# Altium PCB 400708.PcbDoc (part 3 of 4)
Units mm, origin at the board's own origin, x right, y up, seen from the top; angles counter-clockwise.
Board outline 117 x 63.5 mm, 4 copper layers (Top Layer, Mid-Layer 1, Mid-Layer 2, Bottom Layer), stack 1.556 mm thick; 207 components, 162 nets, 822 pads, 1266 vias.
Unrouted connection lines stored in the file: 43.

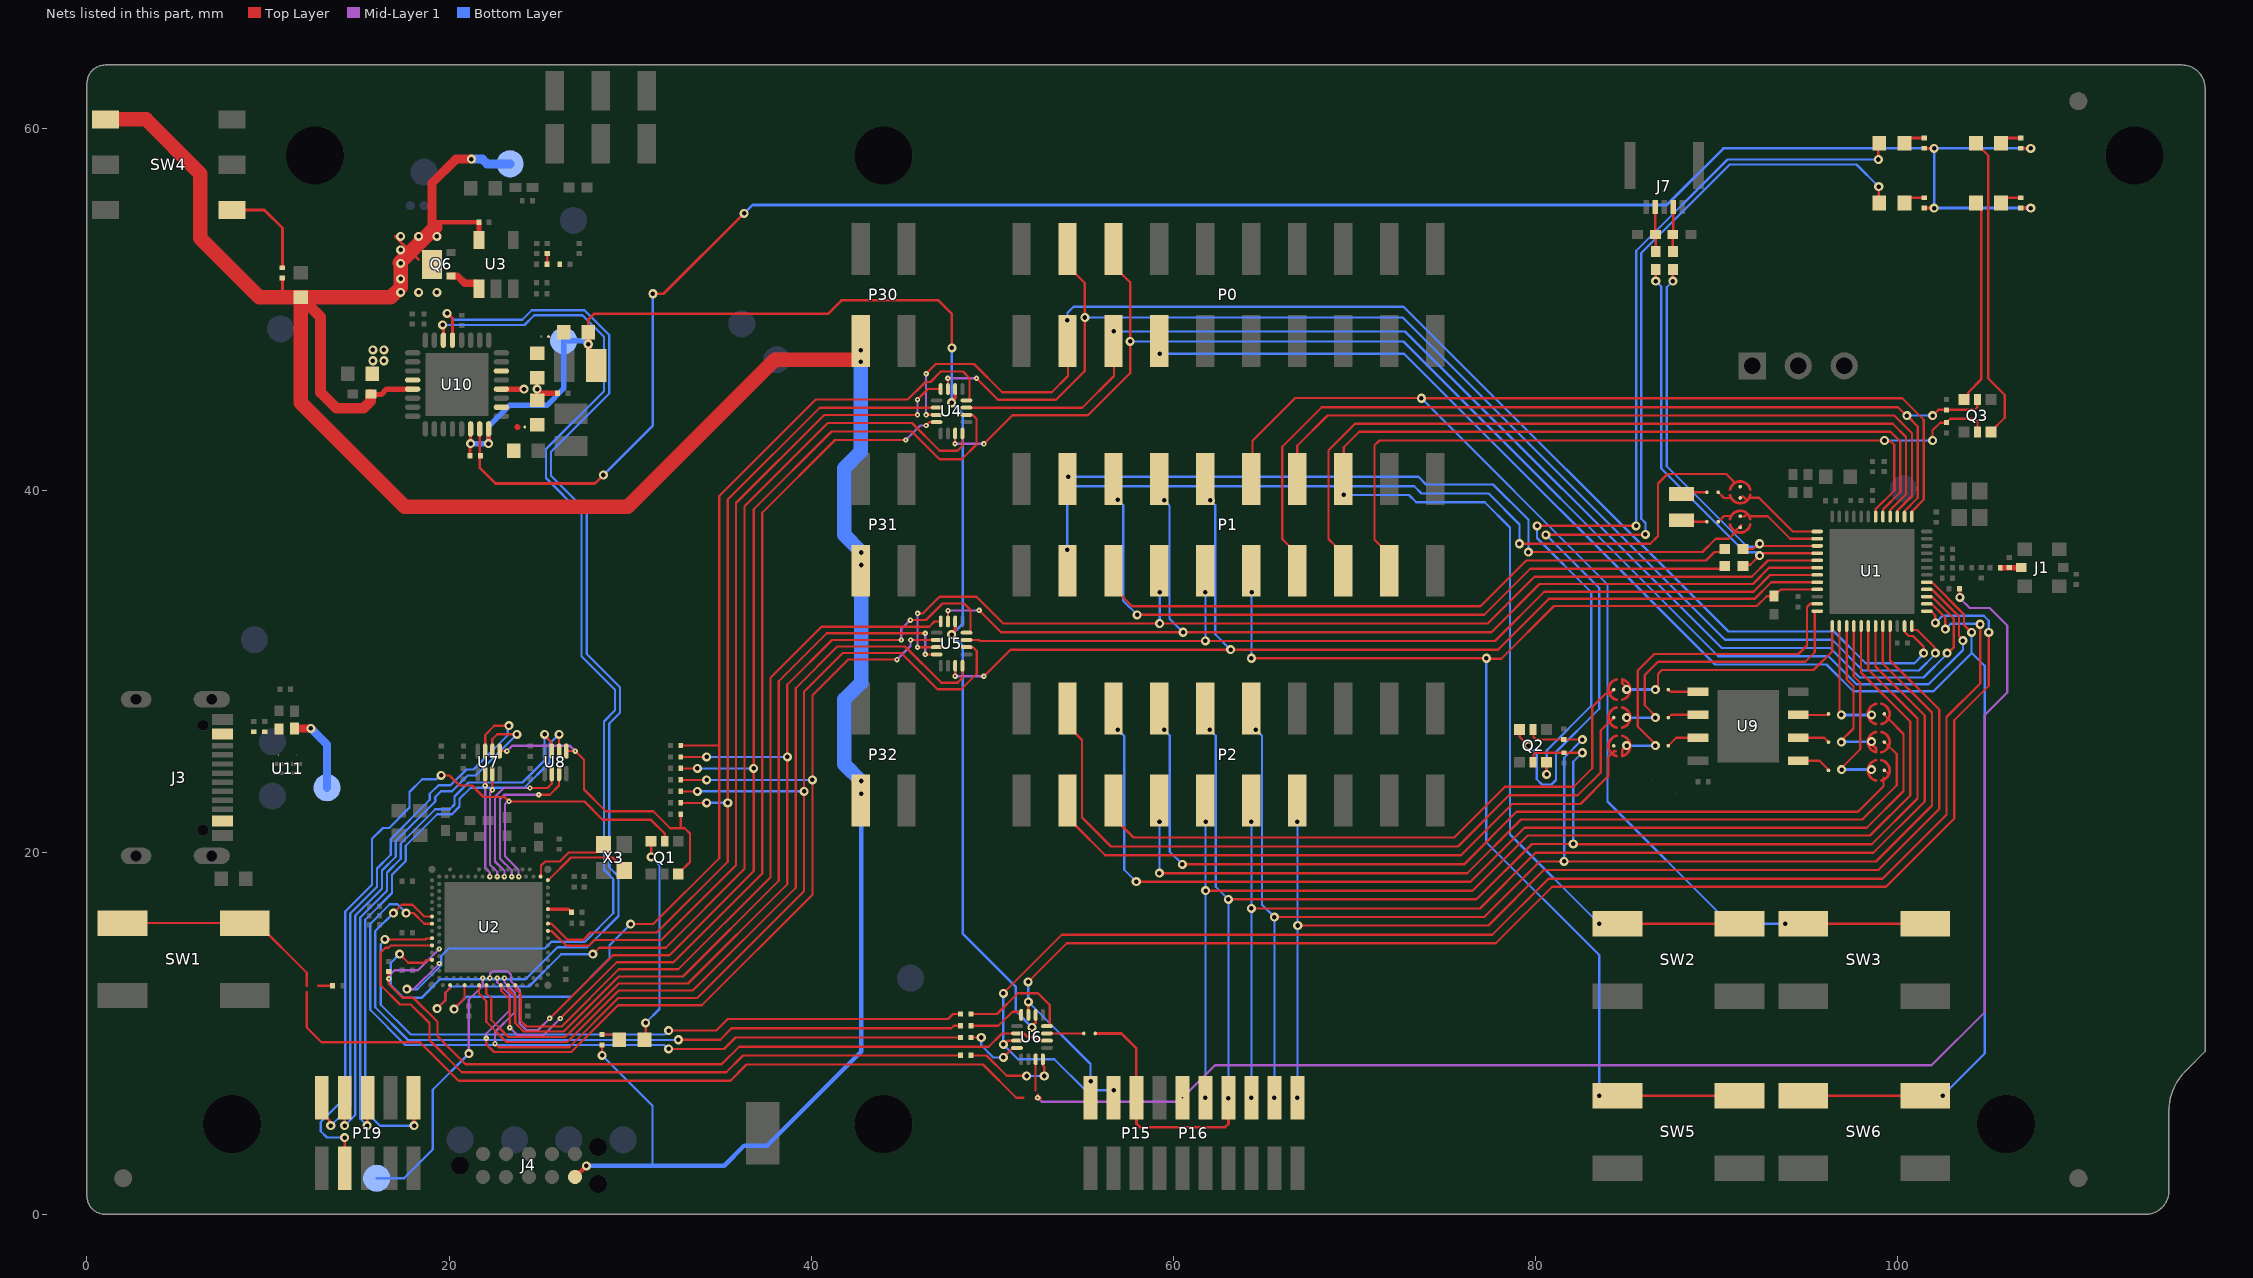
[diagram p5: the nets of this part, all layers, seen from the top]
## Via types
v1: diameter 0.5, hole 0.25, Top Layer to Bottom Layer, tented both sides, 1159 vias
v2: diameter 0.3, hole 0.1, Top Layer to Mid-Layer 1, tented top, 61 vias
v3: diameter 0.61, hole 0.305, Top Layer to Bottom Layer, tented both sides, 28 vias
v4: diameter 0.61, hole 0.305, Top Layer to Bottom Layer, 9 vias
v5: diameter 0.3, hole 0.1, Top Layer to Mid-Layer 1, tented both sides, 9 vias

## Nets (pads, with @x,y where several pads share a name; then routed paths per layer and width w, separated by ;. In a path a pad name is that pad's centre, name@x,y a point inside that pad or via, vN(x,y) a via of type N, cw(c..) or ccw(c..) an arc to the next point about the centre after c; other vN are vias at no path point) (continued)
NetLD1_1: LD1.1 Q1.6 | length 11.5
  Top Layer w0.125: LD1.1@30.865,9.716 v1(30.865,10.588)
  Top Layer w0.15: LD1.1@30.802,9.652 LD1.1@30.865,9.716 ; v1(31.165,19.75) Q1.6@31.165,20.615
  Bottom Layer w0.125: v1(30.865,10.588) 31.627,11.35 31.627,19.287 v1(31.165,19.75)
NetLD1_2: LD1.2 R5.1 | length 0.9
  Top Layer w0.125: R5.1@28.579,9.937 29.12,9.937 LD1.2@29.405,9.652
NetLD2_1: LD2.1 Q2.6 | length 53.7
  Top Layer w0.125: v1(80.106,38.04) 80.11,38.044 v1(85.582,38.044) ; v1(80.634,24.308) Q2.6@80.634,24.985
  Top Layer w0.15: v1(98.955,58.278) 98.955,59.127 LD2.1@99.01,59.182
  Bottom Layer w0.125: v1(80.106,38.04) 80.106,37.375 83.105,34.376 83.105,28.108 80.634,25.637 v1(80.634,24.308) ; v1(85.582,38.044) 85.582,53.231 90.629,58.278 v1(98.955,58.278)
NetLD2_2: LD2.2 R19.1 | length 1.2
  Top Layer w0.15: LD2.2@100.407,59.182 100.692,59.467 R19.1@101.487,59.467
NetLD3_1: LD3.1 Q3.6 | length 16.9
  Top Layer w0.125: LD3.1@104.344,59.182 104.344,59.157 104.663,58.838 104.688,58.838 104.997,58.529 105.034,58.492 105.034,46.174 105.935,45.273 105.935,44.005 Q3.6@105.185,43.255
NetLD3_2: LD3.2 R20.1 | length 1.2
  Top Layer w0.15: LD3.2@105.741,59.182 106.026,59.467 R20.1@106.821,59.467
NetLD4_1: LD4.1 Q2.3 | length 57.9
  Top Layer w0.125: Q2.3@79.134,26.785 79.155,26.763 79.155,26.37 v1(79.63,25.896) ; v1(80.598,37.544) 86.071,37.544 v1(86.09,37.563)
  Top Layer w0.15: v1(98.98,56.778) 98.98,55.91 LD4.1@99.01,55.88
  Bottom Layer w0.125: v1(79.63,25.896) 80.084,25.441 80.084,24.046 80.381,23.749 80.903,23.749 81.157,24.003 81.157,25.553 83.535,27.93 83.535,34.607 v1(80.598,37.544) ; v1(86.09,37.563) 86.09,38.202 85.857,38.434 85.857,53.117 90.743,58.003 97.755,58.003 v1(98.98,56.778)
NetLD4_2: LD4.2 R1.1 | length 0.8
  Top Layer w0.15: LD4.2@100.692,56.165 R1.1@101.487,56.165
NetLD5_1: LD5.1 Q3.3 | length 11.4
  Top Layer w0.125: Q3.3@103.685,45.03 103.918,45.263 103.918,45.412 104.653,46.147 ; LD5.1@104.344,55.88 104.648,55.577 104.648,46.147
NetLD5_2: LD5.2 R2.1 | length 0.8
  Top Layer w0.15: LD5.2@106.026,56.165 R2.1@106.821,56.165
NetP1_5: P1.5 R33.2 | length 36.7
  Top Layer w0.125: P1.5@56.729,35.877 56.729,34.607 57.734,33.603 76.985,33.603 79.509,36.128 89.44,36.128 89.903,36.591 90.309,36.591 R33.2@90.474,36.755
NetP1_6: P1.6 R34.2 | length 41.6
  Top Layer w0.125: P1.6@56.704,40.64 56.704,39.721 v1(56.95,39.475) ; v1(58.012,33.128) 77.181,33.128 79.726,35.672 90.316,35.672 R34.2@90.474,35.83
  Bottom Layer w0.125: v1(56.95,39.475) 57.25,39.175 57.25,33.89 v1(58.012,33.128)
NetP2_3: P2.3 SB17.1 | length 35.4
  Top Layer w0.125: P2.3@54.189,23.177 54.189,21.907 P2.3@54.61,21.487 ; P2.3@54.61,21.487 56.248,19.849 75.903,19.849 78.73,22.676 82.5,22.676 84.042,24.219 84.042,25.272 84.233,25.463
  Top Layer w0.152: 84.233,25.463 84.354,25.584 84.443,25.584
NetP2_4: P2.4 SB18.1 | length 40.3
  Top Layer w0.125: P2.4@54.189,27.556 54.189,26.988 54.61,26.567 54.968,26.209 54.968,21.932 56.571,20.329 75.733,20.329 78.556,23.152 82.35,23.152 83.618,24.42 83.618,26.731 84.1,27.213
  Top Layer w0.152: 84.1,27.213 SB18.1@84.34,27.453
NetP2_5: P2.5 SB19.1 | length 34.5
  Top Layer w0.125: P2.5@56.729,22.956 56.729,21.908 57.15,21.487 57.809,20.828 75.532,20.828 78.335,23.631 82.132,23.631 83.158,24.657 83.158,28.037 83.877,28.756 84.1,28.756
  Top Layer w0.152: 84.1,28.756 SB19.1@84.34,28.996
NetP2_6: P2.6 SB20.1 | length 58.8
  Top Layer w0.125: v1(57.965,18.382) 76.424,18.382 79.406,21.364 98.319,21.364 100.353,23.397 100.353,26.547 99.53,27.37 SB20.1@99.29,27.61
  Top Layer w0.15: P2.6@56.729,27.556 56.729,26.996 v1(56.95,26.775)
  Bottom Layer w0.125: v1(56.95,26.775) 57.3,26.425 57.3,19.046 v1(57.965,18.382)
NetP2_7: P2.7 SB21.1 | length 48.3
  Top Layer w0.125: v1(59.241,18.853) 76.244,18.853 79.212,21.821 98.074,21.821 99.968,23.715 99.968,25.433 99.53,25.871 SB21.1@99.29,26.111
  Bottom Layer w0.125: v1(59.241,18.853) 59.245,18.857 59.245,21.696 v1(59.248,21.7)
NetP2_8: P2.8 SB22.1 | length 49.2
  Top Layer w0.125: v1@60.516,19.34 76.069,19.34 78.973,22.244 97.827,22.244 99.238,23.655 99.238,24.008 99.292,24.062 99.298,24.069 99.236,24.13 ; SB22.1@99.29,24.562 99.53,24.322
  Bottom Layer w0.125: v1(59.5,26.775) 59.819,26.456 59.819,20.037 v1(60.515,19.341)
NetQ1_3: Q1.3 R8.1 U7.5 U8.5 | length 17.4
  Top Layer w0.125: U7.5@22.795,25.599 v2@23.189,25.599 ; U8.5@26.478,25.599 v2(26.969,25.599) 26.971,25.599 27.454,25.116 27.454,23.477 28.656,22.275 31.288,22.275 32.227,21.336 32.772,21.336 ; Q1.3@32.665,18.815 33.316,19.467 33.316,21.044 33.024,21.336 32.772,21.336 ; R8.1@32.801,22.098 32.801,21.365 32.772,21.336
  Mid-Layer 1 w0.125: v2(23.195,25.599) 23.482,25.886 26.682,25.886 v2(26.969,25.599)
NetQ6_1: Q6.1 U3.1 | length 2
  Top Layer w0.4: Q6.1@20.099,51.836 20.474,51.836 20.874,51.436 21.549,51.436 21.649,51.336 U3.1@21.649,51.136
NetR1_2: R1.2 R2.2 R19.2 R20.2 R54.1 U10.31 | length 111
  Top Layer w0.15: U10.31@21.692,43.396 21.692,41.255 22.567,40.379 28.054,40.379 v1(28.525,40.85) ; v1(31.257,50.861) 31.849,50.861 36.293,55.305 v1(36.304,55.305) ; R1.2@101.487,55.595 v1(102.042,55.595) ; R19.2@101.487,58.897 v1(102.042,58.897) ; R2.2@106.821,55.595 v1(107.376,55.595) ; R20.2@106.821,58.897 v1(107.376,58.897)
  Bottom Layer w0.15: v1(28.525,40.85) 31.257,43.582 v1(31.257,50.861) ; v1(36.304,55.305) 36.762,55.763 87.267,55.763 90.401,58.897 v1(102.042,58.897) ; v1(107.376,55.595) v1(102.042,55.595) v1(102.042,58.897) ; v1(107.376,58.897) v1(102.042,58.897)
NetR4_2: R4.2 U6.16 | length 3.3
  Top Layer w0.125: R4.2@48.835,10.425 50.342,10.425 51.121,11.204 51.572,11.204 51.604,11.172 U6.16@51.604,11.025
NetR7_1: R7.1 U2.L31 | length 1.4
  Top Layer w0.187: U2.L31@25.46,16.864 26.597,16.864 26.719,16.743 26.734,16.743 26.775,16.702 R7.1@26.775,16.687
NetR9_2: R9.2 U6.4 | length 3.5
  Top Layer w0.125: R9.2@48.835,9.776 v1(49.402,9.776) ; v1(50.619,8.676) 51.142,9.2 U6.4@51.379,9.2
  Bottom Layer w0.125: v1(49.402,9.776) 49.402,9.344 50.069,8.676 v1(50.619,8.676)
NetR23_1: R23.1 SB8.2 | length 0.8
  Top Layer w0.125: 12.763,12.635 12.764,12.634 12.937,12.634 R23.1@13.569,12.634
NetR31_2: R31.2 R32.2 R35.1 | length 0.5
  Top Layer w0.125: R31.2@25.424,52.595 R32.2@25.424,53.076
NetR36_1: R36.1 SW4.4 | length 5.8
  Top Layer w0.15: SW4.4@8.29,55.219 SW4.4@8.021,55.488 9.794,55.488 10.799,54.483 R36.1@10.799,52.296
NetR37_2: R37.2 U6.12 | length 6.4
  Top Layer w0.125: R37.2@48.835,11.075 50.268,11.075 51.411,12.218 52.539,12.218 53.189,11.568 53.189,10.444 53.146,10.4 U6.12@53.029,10.4
NetR38_2: R38.2 U6.8 | length 5.5
  Top Layer w0.125: R38.2@48.835,8.784 49.685,8.784 50.812,7.657 51.895,7.657 v1(51.902,7.65) ; U6.8@52.804,8.575 52.822,8.557 52.822,8.22 52.882,8.16 v1(52.882,7.65)
  Bottom Layer w0.125: v1(51.902,7.65) v1(52.882,7.65)
NetSB1_2: SB1.2 SB2.1 SB8.1 SW1.2 | length 55.9
  Top Layer w0.125: SW1.2@1.963,16.097 SW1.2@8.713,16.097 9.388,16.097 12.138,13.347 12.138,12.988 12.138,12.635 ; 12.138,12.282 12.138,10.328 12.95,9.516 18.401,9.516 20.523,7.393 35.55,7.393 36.439,8.282 49.5,8.282 51.332,6.45 51.718,6.45
NetSB3_2: SB3.2 X1.2 | length 1.4
  Top Layer w0.125: X1.2@88.081,39.799 88.175,39.893 SB3.2@89.488,39.893
NetSB4_2: SB4.2 X1.1 | length 1.4
  Top Layer w0.125: X1.1@88.081,38.349 88.162,38.267 SB4.2@89.488,38.267
NetSB11_2: SB11.2 U9.1 | length 1.9
  Top Layer w0.125: U9.1@94.536,25.066 95.708,25.066 SB11.2@96.203,24.571
NetSB12_2: SB12.2 U9.6 | length 1.7
  Top Layer w0.125: SB12.2@87.353,27.446 87.513,27.606 U9.6@88.996,27.606
NetSB13_2: SB13.2 U9.5 | length 1.7
  Top Layer w0.125: SB13.2@87.353,28.996 87.473,28.876 U9.5@88.996,28.876
NetSB14_2: SB14.2 U9.2 | length 1.8
  Top Layer w0.125: U9.2@94.536,26.336 95.963,26.336 SB14.2@96.203,26.096
NetSB15_2: SB15.2 U9.3 | length 1.7
  Top Layer w0.125: U9.3@94.536,27.606 94.546,27.596 SB15.2@96.203,27.596
NetSB16_2: SB16.2 U9.7 | length 1.8
  Top Layer w0.125: SB16.2@87.353,25.896 87.793,26.336 U9.7@88.996,26.336
NetSB24_1: SB24.1 U6.11 | length 2
  Top Layer w0.125: U6.11@53.029,10 SB24.1@55.067,10
NetTP7_1: TP7.1 U2.AK14 | length 14.4
  Mid-Layer 1 w0.125: v1(21.097,8.889) 21.092,8.895 21.092,11.861 21.86,12.629 v2(21.86,13.064)
  Bottom Layer w0.125: TP7.1@16.004,2 17.52,2 19.104,3.584 19.104,6.897 v1(21.097,8.889)
NetU2_B30: U2.B30 X3.3 | length 4.6
  Top Layer w0.125: U2.B30@25.06,18.664 25.079,18.684 25.079,18.754 25.085,18.76 25.085,19.273 25.315,19.502 26.123,19.502 26.61,19.99 28.127,19.99 28.531,20.394 X3.3@28.531,20.444
NetU2_C31: U2.C31 X3.1 | length 5.1
  Top Layer w0.125: U2.C31@25.46,18.464 25.485,18.464 26.735,19.715 29.027,19.715 29.681,19.061 X3.1@29.681,18.994
NFC1: C17.1 J7.2 R21.2 | length 2.5
  Top Layer w0.125: R21.2@87.604,53.204 C17.1@87.604,54.123 87.629,54.148 J7.2@87.629,55.654
NFC2: C19.2 J7.4 R22.2 | length 2.5
  Top Layer w0.125: J7.4@86.629,55.654 86.629,54.146 C19.2@86.652,54.123 86.661,54.114 R22.2@86.661,53.204
nRF54L15_RESET: P15.10 P16.10 R3.2 SB1.1 U6.7 | length 82.3
  Top Layer w0.125: v2@52.404,6.379 v2@52.404,6.45 ; 52.404,6.866 U6.7@52.404,8.575 ; v2(52.515,6.45) 52.518,6.447 52.671,6.447 52.691,6.427 v2@52.593,6.427 ; R3.2@103.435,34.575 103.447,34.563 103.447,34.105 v1(103.459,34.093)
  Top Layer w0.15: v2(52.515,6.45) 52.515,6.608 52.517,6.61
  Mid-Layer 1 w0.125: v2(52.515,6.45) 52.742,6.223 60.291,6.223 v2(60.518,6.45) 62.308,8.239 101.896,8.239 104.835,11.178 104.835,27.598 106.077,28.84 106.077,32.531 105.108,33.5 104,33.5 103.459,34.041 v1(103.459,34.093)
P0.00: P0.3 U1.23 U4.3 | length 73.4
  Top Layer w0.125: v2(46.353,44.171) U4.3@46.935,44.171 ; v2(46.353,46.446) 46.887,46.98 49,46.98 50.559,45.421 53.293,45.421 54.189,46.317 54.189,48.577 54.154,48.613 54.154,49.393 v1(54.164,49.403) ; U1.23@100.414,32.496 100.414,32.172 100.633,31.953 100.875,31.953 101.453,31.375 101.453,31.007 v1(101.455,31.005)
  Mid-Layer 1 w0.125: v2(46.353,44.171) v2(46.353,46.446)
  Bottom Layer w0.125: v1(54.164,49.403) 54.164,49.814 54.5,50.15 72.73,50.15 90.682,32.198 96.512,32.198 98.255,30.455 100.956,30.455 101.455,30.954 v1(101.455,31.005)
P0.01: P0.4 U1.24 U4.15 | length 74
  Top Layer w0.125: U4.15@47.56,45.597 v2(47.559,46.193) ; v2(49.139,46.193) 50.326,45.006 53.531,45.006 55.125,46.601 55.125,51.452 54.61,51.967 54.189,52.388 P0.4@54.189,53.222 ; U1.24@100.805,32.505 100.805,32.307 100.828,32.284 101.102,32.284 102.057,31.328 102.057,31.053 v1(102.105,31.005)
  Mid-Layer 1 w0.125: v2(47.559,46.193) v2(49.139,46.193)
  Bottom Layer w0.125: v1(55.125,49.55) 72.686,49.55 90.493,31.743 96.408,31.743 98.103,30.048 101.203,30.048 102.105,30.951 v1(102.105,31.005)
P0.02: P0.5 U1.27 U4.11 | length 69.9
  Top Layer w0.125: U4.11@48.585,44.571 54.983,44.571 56.729,46.317 v1(56.729,48.778) ; U1.27@101.639,34.121 101.885,34.121 101.913,34.093 101.944,34.093 103.13,32.906 103.13,31.343 102.795,31.007 v1(102.76,31.007)
  Bottom Layer w0.125: v1(56.729,48.778) 72.815,48.778 90.305,31.288 96.304,31.288 97.925,29.667 101.448,29.667 102.76,30.979 v1(102.76,31.007)
P0.03: P0.6 U1.28 U4.7 | length 78
  Top Layer w0.125: v2@47.955,42.582 U4.7@47.955,43.141 ; U4.7@47.964,43.125 U4.7@47.971,43.118 ; v2(49.545,42.564) 51.127,44.146 55.296,44.146 57.625,46.475 57.625,51.492 56.729,52.388 P0.6@56.729,53.222 ; U1.28@101.63,34.53 101.876,34.53 101.913,34.493 101.946,34.493 103.411,33.027 103.411,31.966 103.63,31.747 v1(103.63,31.705)
  Top Layer w0.152: v2(47.95,42.577) v2@47.955,42.582
  Mid-Layer 1 w0.125: v2(47.95,42.577) 47.957,42.571 v2@49.539,42.571
  Bottom Layer w0.125: v1(57.625,48.225) 72.724,48.225 90.116,30.833 96.201,30.833 97.747,29.286 101.733,29.286 103.63,31.183 v1(103.63,31.705)
P0.04: P0.7 SW6.2 U1.29 | length 93
  Top Layer w0.125: U1.29@101.639,34.921 101.885,34.921 101.913,34.893 101.944,34.893 103.694,33.142 103.694,32.566 v1(104.105,32.155)
  Top Layer w0.15: v1(59.269,47.549) P0.7@59.269,48.577 ; SW6.2@94.804,6.558 v1(102.504,6.558)
  Bottom Layer w0.125: v1(59.269,47.549) 72.757,47.549 89.928,30.378 96.097,30.378 97.57,28.905 102.01,28.905 104.105,31.001 104.105,31.034 ; v1(102.504,6.558) 104.835,8.888 104.835,30.305 104.105,31.034 ; v1(104.105,32.155) 104.105,31.034
P1.00: P1.3 SB5.2 | length 45.6
  Top Layer w0.125: v1@79.109,37.076 v1(79.134,37.052) v1(79.134,37.052) 86.358,37.053 86.782,37.477 86.782,40.38 87.31,40.908 90.558,40.908 91.045,40.421
  Bottom Layer w0.125: v1(54.15,36.725) 54.15,39.825 54.55,40.225 73.326,40.225 73.726,39.825 77.431,39.825 79.134,38.122 v1(79.134,37.052)
P1.00/XL1: SB3.1 SB5.1 U1.1 | length 5.8
  Top Layer w0.125: SB3.1@90.112,39.893 90.425,39.581 90.826,39.581 ; SB5.1@91.324,39.581 91.338,39.581 91.402,39.645 91.513,39.645 91.714,39.444 91.715,39.443 ; 91.863,39.591 92.37,39.591 94.231,37.73 U1.1@95.58,37.73
P1.01: P1.4 SB6.2 | length 40.7
  Top Layer w0.125: v1(79.63,36.591) 89.242,36.591 89.981,37.33 90.69,37.33 91.062,37.703 ; 91.045,37.74 91.383,38.078 ; 91.077,37.708 91.088,37.718
  Top Layer w0.15: P1.4@54.164,40.64 54.2,40.676 v1(54.2,40.75)
  Bottom Layer w0.125: v1(54.2,40.75) 73.55,40.75 73.975,40.325 77.676,40.325 79.63,38.371 v1(79.63,36.591)
P1.01/XL2: SB4.1 SB6.1 U1.2 | length 5.8
  Top Layer w0.125: SB4.1@90.112,38.267 90.425,38.58 90.826,38.58 ; SB6.1@91.324,38.58 91.334,38.57 91.369,38.57 91.384,38.555 91.568,38.555 91.722,38.709 ; 91.697,38.734 91.722,38.709 ; 91.723,38.71 91.722,38.709 ; U1.2@95.58,37.33 94.091,37.33 92.851,38.57 91.861,38.57 91.85,38.581 91.722,38.709
P1.02/NFC1: R21.1 R33.1 U1.3 | length 22.2
  Top Layer w0.125: v1(87.604,51.554) R21.1@87.604,52.204 ; R33.1@91.577,36.755 92.043,36.755 92.34,37.052 v1(92.399,37.052) 92.494,37.052 92.615,36.93 U1.3@95.58,36.93
  Bottom Layer w0.125: v1(87.604,51.554) 87.264,51.214 87.264,41.339 91.722,36.881 92.228,36.881 v1(92.399,37.052)
P1.03/NFC2: R22.1 R34.1 U1.4 | length 23.1
  Top Layer w0.125: v1(86.661,51.554) R22.1@86.661,52.204 ; R34.1@91.327,35.83 91.384,35.887 91.888,35.887 v1(92.399,36.398) 92.493,36.398 92.625,36.53 U1.4@95.58,36.53
  Bottom Layer w0.125: v1(86.661,51.554) 86.959,51.256 86.959,41.213 91.595,36.576 92.221,36.576 v1(92.399,36.398)
P1.04: P1.7 U1.5 U5.3 | length 56.8
  Top Layer w0.125: v2(45.881,31.336) U5.3@46.939,31.336 ; v2(45.887,33.201) 46.166,33.201 47.09,34.125 49.139,34.125 50.619,32.645 v1(59.257,32.645) 77.381,32.645 79.965,35.229 91.967,35.229 92.858,36.121 U1.5@95.571,36.121
  Mid-Layer 1 w0.125: v2(45.881,31.336) 45.884,31.339 45.884,33.198 v2(45.887,33.201)
  Bottom Layer w0.125: v1(59.257,32.645) 59.263,32.652 59.263,34.369 v1(59.269,34.375)
P1.05: P1.8 U1.6 U5.15 | length 59.6
  Top Layer w0.125: U5.15@47.564,32.762 v2(47.563,33.358) ; v2(49.28,33.378) 50.496,32.163 v1(60.552,32.163) 77.581,32.163 80.246,34.828 92.028,34.828 92.922,35.721 U1.6@95.571,35.721 ; P1.8@59.244,40.64 59.244,39.706 v1(59.5,39.45)
  Mid-Layer 1 w0.125: v2(47.563,33.358) 47.573,33.368 49.27,33.368 v2(49.28,33.378)
  Bottom Layer w0.125: v1(59.5,39.45) 59.8,39.15 59.8,32.915 v1(60.552,32.163)
P1.06: P1.9 U1.7 U5.11 | length 51.2
  Top Layer w0.125: U5.11@48.589,31.736 49.28,31.736 49.336,31.68 77.781,31.68 80.507,34.406 92.058,34.406 92.973,35.321 U1.7@95.571,35.321
  Bottom Layer w0.125: v1(61.784,34.375) 61.786,34.374 v1(61.787,31.68) v1(61.787,31.68)
P1.07: P1.10 U1.8 U5.7 | length 60.4
  Top Layer w0.125: v2@47.959,29.748 U5.7@47.959,30.306 ; v2(49.549,29.729) 51.02,31.2 77.946,31.2 80.752,34.006 92.111,34.006 93.035,34.93 U1.8@95.58,34.93 ; P1.10@61.784,40.64 61.784,39.716 v1(62.05,39.45)
  Top Layer w0.152: v2(47.954,29.743) v2@47.959,29.748 ; U5.7@47.959,30.306 U5.7@47.964,30.311
  Mid-Layer 1 w0.125: v2(47.954,29.743) 47.96,29.736 49.543,29.736 v2(49.549,29.729)
  Bottom Layer w0.125: v1(62.05,39.45) 62.325,39.175 62.325,32.05 v1(63.175,31.2)
P1.08: C41.2 P1.11 SW5.2 U1.9 | length 71
  Top Layer w0.125: v1(64.325,30.725) v1(77.3,30.725) ; v1@77.3,30.7 78.128,30.7 81.036,33.608 92.241,33.608 92.788,34.155 C41.2@93.186,34.155 93.561,34.53 U1.9@95.58,34.53
  Top Layer w0.15: v1(83.535,6.558) SW5.2@91.293,6.558
  Bottom Layer w0.125: v1(64.325,30.725) 64.334,30.734 64.334,34.366 v1(64.342,34.375) ; v1(77.3,30.725) 77.3,20.562 83.535,14.327 v1(83.535,6.558)
P1.09: P1.12 SW3.2 U1.37 | length 93.5
  Top Layer w0.125: P1.12@64.349,40.322 64.389,40.363 64.389,42.739 66.75,45.1 73.707,45.1 v1(73.718,45.089) ; v1@73.729,45.1 73.736,45.093 100.271,45.093 101.465,43.9 101.465,39.49 100.814,38.839 100.814,38.564 U1.37@100.805,38.555
  Top Layer w0.152: v1(93.804,16.058) SW3.2@101.554,16.058
  Bottom Layer w0.125: v1(73.718,45.089) 83.986,34.821 ; 83.992,34.821 83.992,22.813 90.747,16.058 v1(93.804,16.058)
P1.10: P1.13 Q3.2 R11.1 U1.38 | length 52.8
  Top Layer w0.125: P1.13@66.889,36.195 66.419,36.666 66.419,36.933 66.032,37.319 66.032,42.403 68.214,44.585 100.049,44.585 100.504,44.13 v1(100.535,44.13) 101.14,43.525 101.14,39.617 ; U1.38@100.405,38.555 100.415,38.565 100.415,38.866 101.14,39.591 ; v1(101.955,44.13) 102.274,44.449 R11.1@102.723,44.449 104.278,44.449 104.42,44.591 104.42,45.016 Q3.2@104.435,45.03
  Bottom Layer w0.125: v1(100.535,44.13) v1(101.955,44.13)
P1.11: P1.14 U1.39 | length 43.4
  Top Layer w0.125: P1.14@66.526,41.956 P1.14@66.889,41.956 ; P1.14@66.864,40.64 P1.14@66.864,41.605 ; P1.14@66.864,41.956 66.864,42.464 68.53,44.13 99.839,44.13 100.815,43.154 100.815,39.692 100.014,38.891 U1.39@100.014,38.564 ; P1.14@66.889,40.322 66.889,40.64 66.889,41.592 66.902,41.605 P1.14@66.902,41.943
P1.12: P1.15 U1.40 | length 43.9
  Top Layer w0.125: P1.15@69.429,36.195 68.959,36.666 68.959,36.941 68.582,37.318 68.582,42.223 70.044,43.685 99.758,43.685 100.49,42.953 100.49,39.792 99.615,38.918 U1.40@99.615,38.565
P1.13: P1.16 SW2.2 U1.41 | length 79.8
  Top Layer w0.125: P1.16@69.429,40.64 69.429,42.379 70.289,43.239 99.626,43.239 100.165,42.7 100.165,39.892 99.215,38.942 U1.41@99.215,38.565
  Top Layer w0.15: v1(69.425,39.75) P1.16@69.425,40.318 ; v1(83.535,16.058) SW2.2@91.293,16.058
  Bottom Layer w0.125: v1(69.425,39.75) 73.029,39.75 73.436,39.343 77.216,39.343 78.604,37.955 78.604,20.988 v1(83.535,16.058)
P1.14: P1.17 Q3.5 R27.1 U1.42 | length 46.9
  Top Layer w0.125: P1.17@71.969,35.877 71.969,36.462 71.499,36.933 71.467,36.933 71.125,37.275 71.125,42.49 71.395,42.759 v1@99.294,42.759 ; U1.42@98.815,38.565 98.815,38.966 99.835,39.986 99.835,42.517 99.633,42.718 99.335,42.718 v1(99.298,42.755) ; v1(101.955,42.755) 101.955,43.317 102.379,43.74 R27.1@102.723,43.74 102.738,43.74 102.798,43.8 102.798,43.815 102.938,43.955 104.299,43.955 104.435,43.819 Q3.5@104.435,43.23
  Bottom Layer w0.125: v1(99.298,42.755) v1(101.955,42.755)
P2.00: SB16.1 SB17.2 U1.11 | length 19.5
  Top Layer w0.125: SB16.1@86.728,25.896 85.668,26.956 85.668,30.048 86.582,30.963 94.544,30.963 95.017,31.436 95.017,33.561 95.187,33.73 U1.11@95.58,33.73
  Top Layer w0.152: 84.805,25.328 84.805,25.651 v1(85.049,25.896)
  Bottom Layer w0.152: v1(85.049,25.896) v1(86.643,25.896)
P2.01: SB12.1 SB18.2 U1.12 | length 16.6
  Top Layer w0.125: SB12.1@86.728,27.446 86.049,28.125 86.049,29.794 86.786,30.531 94.915,30.531 95.438,31.054 95.438,33.295 95.473,33.33 U1.12@95.58,33.33
  Bottom Layer w0.15: v1(85.049,27.446) v1@86.715,27.446
  other v1: 86.643,27.446
P2.02: SB13.1 SB19.2 U1.13 | length 14.8
  Top Layer w0.125: SB13.1@86.779,28.956 86.779,29.857 86.996,30.073 95.373,30.073 96.405,31.106 U1.13@96.405,32.505
  Top Layer w0.152: 84.805,29.552 84.805,29.37 85.049,29.125 v1(85.049,29.003)
  Bottom Layer w0.152: v1(85.049,29.003) 85.053,28.999 86.709,28.999 v1@86.712,29.003
  other v1: 86.646,28.996
P2.03: SB15.1 SB20.2 U1.14 | length 6.5
  Top Layer w0.125: SB15.1@96.805,27.654 U1.14@96.805,32.505
  Bottom Layer w0.15: v1@96.919,27.613 96.936,27.596 v1(98.58,27.596)
  other v1: 96.918,27.596
P2.04: SB14.1 SB21.2 U1.15 | length 9.2
  Top Layer w0.125: SB14.1@96.828,26.096 97.581,26.848 97.581,29.175 97.205,29.55 U1.15@97.205,32.505
  Top Layer w0.152: v1(98.58,26.123) 98.58,26 98.824,25.756 98.824,25.555
  Bottom Layer w0.15: v1(96.918,26.096) 96.932,26.109 98.567,26.109 v1(98.58,26.123)
P2.05: SB11.1 SB22.2 U1.16 | length 10.3
  Top Layer w0.125: SB11.1@96.828,24.571 97.957,25.699 97.957,29.378 97.605,29.73 U1.16@97.605,32.505
  Bottom Layer w0.152: v1@96.805,24.582 96.924,24.582 96.932,24.574 v1(98.58,24.574)
  other v1: 96.924,24.571
P2.06: P2.9 P16.12 U1.17 | length 66.8
  Top Layer w0.125: v1(61.795,17.887) 76.541,17.887 79.586,20.932 98.501,20.932 100.718,23.149 100.718,27.228 98.005,29.94 U1.17@98.005,32.505
  Bottom Layer w0.125: v1(61.788,6.45) 61.788,17.887 61.795,17.894 v1(61.795,21.7)
P2.07: P2.10 P15.6 P16.6 P16.14 Q2.5 R12.1 SB24.2 U1.18 | length 93.9
  Top Layer w0.125: v1(63.051,17.411) 76.765,17.411 79.821,20.467 v1(82.104,20.467) 82.114,20.457 98.592,20.457 101.118,22.983 101.118,27.393 98.405,30.106 U1.18@98.405,32.505 ; Q2.5@79.884,24.985 79.913,25.014 79.913,25.399 80.02,25.506 R12.1@81.592,25.506 v1(82.604,25.505)
  Top Layer w0.15: 55.792,9.998 57.137,9.998 57.968,9.167 57.968,6.157 P16.6@57.978,6.147 ; P16.6@57.978,6.45 P16.6@57.978,6.147 ; P16.14@63.058,6.45 v1(63.058,6.427) 63.058,5.007 62.877,4.826 58.17,4.826 57.978,5.018 P16.6@57.978,6.147
  Bottom Layer w0.125: v1(62.025,26.775) 62.354,26.446 62.354,18.108 v1(63.051,17.411) ; v1(63.058,6.427) v1@63.058,17.411 ; v1(82.104,20.467) 82.104,25.005 v1(82.604,25.505)
P2.08: P2.11 P16.16 U1.19 | length 65.7
  Top Layer w0.125: v1(64.321,16.908) 76.952,16.908 80.025,19.981 98.681,19.981 101.518,22.818 101.518,27.559 98.805,30.272 U1.19@98.805,32.505
  Bottom Layer w0.125: v1(64.328,6.45) 64.328,16.908 64.325,16.912 64.325,21.696 v1(64.328,21.7)
P2.09: P2.12 P16.18 Q2.2 R10.1 U1.20 | length 81
  Top Layer w0.125: v1(65.596,16.427) 77.181,16.427 80.257,19.503 81.602,19.503 v1(81.604,19.5) 98.828,19.5 101.918,22.59 101.918,27.725 99.205,30.438 U1.20@99.205,32.505 ; Q2.2@79.884,26.785 79.909,26.759 79.909,26.37 80.041,26.239 82.599,26.239 v1(82.604,26.235)
  Bottom Layer w0.125: v1(64.575,26.785) 64.908,26.451 64.908,17.115 v1(65.596,16.427) ; v1(65.598,6.45) v1@65.598,16.427 ; v1(81.604,19.5) 81.604,25.235 v1(82.604,26.235)
P2.10: P2.13 P16.20 U1.21 | length 64.6
  Top Layer w0.125: v1(66.886,15.963) 77.417,15.963 80.477,19.023 98.947,19.023 102.318,22.393 102.318,27.89 99.605,30.603 U1.21@99.605,32.505
  Bottom Layer w0.125: v1(66.868,6.45) 66.868,15.963 66.877,15.972 66.877,21.691 v1(66.868,21.7)
P3V3: C28.2 L9.1 R54.2 TP10.1 U4.14 U5.14 U6.14 U10.30 U10.32 | length 80.9
  Top Layer w0.15: R54.2@21.164,41.911 v1@21.164,42.551 ; v1@21.192,42.594 U10.30@21.192,43.396 ; C28.2@27.695,48.742 27.695,49.442 28.004,49.75 40.925,49.75 41.675,50.5 47.029,50.5 47.775,49.754 v1(47.775,47.875) ; v1(52.205,10.335) 52.205,10.399 52.404,10.598 U6.14@52.404,11.025
  Top Layer w0.2: v1(47.764,32.026) 47.764,32.107 47.96,32.304 U5.14@47.96,32.757 ; v1(47.764,44.84) 47.764,44.921 47.96,45.117 U4.14@47.96,45.571
  Top Layer w0.25: v1@21.164,42.551 v1(21.199,42.586) v1@21.192,42.594 ; v1(22.181,42.586) 22.192,42.597 U10.32@22.192,43.396
  Top Layer w0.3: v1(27.692,48.071) 27.712,48.051 27.712,47.286 L9.1@28.127,46.871 ; v1@27.717,48.071 C28.2@27.717,48.521
  Bottom Layer w0.15: v1(47.775,47.875) 47.77,47.87 47.77,44.845 v1(47.764,44.84) 48.387,44.217 48.387,32.649 v1(47.764,32.026) 48.385,31.406 48.385,15.501 51.312,12.573 51.312,11.228 v1(52.205,10.335)
  Bottom Layer w0.3: v1@21.199,42.586 v1(22.181,42.586) 22.181,43.526 23.35,44.694 25.401,44.694 26.334,45.627 TP10.1@26.334,48.26 27.449,48.26 27.638,48.071 v1(27.692,48.071)
P5V0: C24.2 C25.2 C26.2 C56.2 U10.4 U10.20 | length 2.3
  Top Layer w0.25: v1(24.867,45.596) 24.907,45.596 25.138,45.365
  Top Layer w0.3: U10.4@22.892,45.596 v1@24.038,45.596 ; 25.138,45.365 C56.2@25.955,45.365
  other v1: 24.142,45.596 15.799,47.161 16.399,47.161 15.799,47.761 16.399,47.761
PVSS1: C24.1 C27.1 NT2.2 U10.2 | length 0
  Top Layer w0.3: 23.78,43.496 23.78,43.508 23.792,43.496
PVSS2: C25.1 C28.1 NT3.2 U10.6
RF: C61.2 J1.1 L4.2 | length 1.1
  Top Layer w0.3: L4.2@105.741,35.73 C61.2@106.2,35.73 J1.1@106.845,35.73
SWD0_CLK: U2.B18 U7.3 | length 5.9
  Top Layer w0.125: v2(22.395,23.455) U7.3@22.395,24.349
  Mid-Layer 1 w0.125: v2(22.395,23.455) 22.395,23.408 22.27,23.283 22.27,19.318 22.66,18.928 v2(22.66,18.664)
SWD0_CLK_EXT: P19.4 U7.6 | length 29.8
  Top Layer w0.125: U7.6@22.395,25.599 22.395,26.254 22.667,26.525 v1(23.754,26.525)
  Top Layer w0.15: v1(14.234,4.906) P19.4@14.234,6.45
  Bottom Layer w0.125: v1(14.234,4.906) 14.821,5.493 14.821,16.513 16.299,17.99 16.299,19.001 17.056,19.758 17.056,20.631 19.234,22.809 19.234,23.056 19.552,23.374 20.16,23.374 21.038,24.252 21.481,24.252 v1(23.754,26.525)
SWD0_IO: U2.B16 U7.2 | length 5.8
  Top Layer w0.125: v2(21.995,23.694) U7.2@21.995,24.349
  Mid-Layer 1 w0.125: v2(21.995,23.694) 21.995,19.149 22.257,18.888 22.257,18.668 v2(22.26,18.664)
SWD0_IO_EXT: P19.2 U7.7 | length 30.9
  Top Layer w0.125: U7.7@21.995,25.599 21.995,26.493 22.506,27.004 v1@23.207,27.004
  Top Layer w0.15: P19.2@12.964,6.45 12.964,5.63 13.399,5.195 13.399,4.973 v1(13.466,4.906)
  Bottom Layer w0.125: v1(13.466,4.906) 14.546,5.986 14.546,16.627 16.024,18.104 16.024,19.115 16.781,19.872 16.781,20.745 18.941,22.905 18.941,23.235 19.414,23.708 20.084,23.708 20.962,24.586 21.349,24.586 23.242,26.48 23.242,26.937 v1(23.308,27.004)
SWD0_RESET: U2.B22 U8.3 | length 8.8
  Top Layer w0.125: v2(24.957,23.19) 25.565,23.19 26.078,23.703 U8.3@26.078,24.349
  Mid-Layer 1 w0.125: v2(23.46,18.664) 23.46,19.017 22.82,19.657 22.82,22.957 23.053,23.19 v2(24.957,23.19)
SWD0_RESET_EXT: P19.10 U8.6 | length 33
  Top Layer w0.125: U8.6@26.078,25.599 v1(26.078,26.524)
  Top Layer w0.15: P19.10@18.044,7.15 P19.10@18.07,7.125 ; v1(18.07,4.906) P19.10@18.07,6.425
  Bottom Layer w0.125: v1(18.07,4.906) 16.19,4.906 15.371,5.725 15.371,16.285 16.849,17.763 16.849,18.773 17.606,19.531 17.606,20.369 19.348,22.11 19.49,22.11 19.491,22.109 20.102,22.109 20.103,22.11 20.16,22.11 20.581,22.53 20.581,22.958 21.194,23.571 24.156,23.571 25.553,24.968 25.553,25.999 v1(26.078,26.524)
SWD0_SEL: P19.3 Q1.5 U2.B24 | length 45
  Top Layer w0.125: v1(19.567,24.252) 20.024,24.252 20.575,23.702 21.268,23.702 21.905,23.065 23.068,23.065 v2(23.314,22.818) ; v2@23.323,22.81 27.487,22.81 28.499,21.798 31.163,21.798 31.915,21.046 Q1.5@31.915,20.615
  Top Layer w0.15: P19.3@14.234,2.55 v1(14.234,4.246)
  Mid-Layer 1 w0.125: v2(23.314,22.818) 23.267,22.818 23.186,22.737 23.169,22.737 23.095,22.664 23.095,19.789 23.835,19.049 23.835,18.689 v2(23.86,18.664)
  Bottom Layer w0.125: v1(14.234,4.246) 13.263,4.246 12.913,4.596 12.913,5.109 14.271,6.468 14.271,16.741 15.749,18.218 15.749,20.754 16.349,21.354 16.699,21.354 17.821,22.475 17.821,23.339 18.522,24.041 19.306,24.041 19.518,24.252 v1(19.567,24.252)
SWD0_SWO: U2.B20 U8.2 | length 8.6
  Top Layer w0.125: v2(24.475,23.558) 25.445,23.558 25.678,23.792 U8.2@25.678,24.349
  Mid-Layer 1 w0.125: v2(23.06,18.664) 23.06,18.986 22.545,19.501 22.545,23.075 23.028,23.558 v2@24.485,23.558
SWD0_SWO_EXT: P19.6 U8.7 | length 30.9
  Top Layer w0.125: P19.6@15.479,7.125 P19.6@15.504,7.15 ; v1(25.278,26.524) 25.278,26.464 25.665,26.077 25.665,25.613 U8.7@25.678,25.599
  Top Layer w0.15: v1(15.479,4.906) P19.6@15.479,6.425
  Bottom Layer w0.125: v1(15.479,4.906) 15.096,5.289 15.096,16.399 16.574,17.876 16.574,18.887 17.331,19.644 17.331,20.482 19.234,22.385 19.604,22.385 ; v1(25.278,26.524) 25.278,25.082 24.057,23.861 21.077,23.861 20.306,23.089 20.306,22.644 20.046,22.385 19.989,22.385 19.988,22.384 19.605,22.384 ; 19.604,22.385 19.605,22.384
SWD3_CLK: R9.1 U2.R1 | length 42.8
  Top Layer w0.125: v1(17.635,16.651) 17.639,16.655 18.038,16.655 18.629,16.064 U2.R1@19.06,16.064 ; v1(32.135,9.144) 35.188,9.144 35.82,9.776 R9.1@48.265,9.776
  Bottom Layer w0.125: v1(17.635,16.651) 17.155,17.131 16.727,17.131 15.646,16.051 15.646,11.304 17.584,9.367 31.875,9.367 32.097,9.144 v1(32.135,9.144)
SWD3_CTRL: R17.2 U2.AB2 U6.2 U6.10 | length 43.8
  Top Layer w0.125: U6.2@51.382,9.998 51.766,9.998 51.959,9.804 52.387,9.804 52.591,9.6 U6.10@53.029,9.6
  Top Layer w0.127: R17.2@16.668,13.411 16.677,13.403 v2(16.677,13.017) 16.677,12.735 17.446,11.965 18.036,11.965 19.358,10.642 19.358,9.846 20.906,8.298 35.059,8.298 36.03,9.269 49.814,9.269 50.543,9.998 U6.2@51.382,9.998
  Mid-Layer 1 w0.127: v2(16.677,13.017) 16.706,13.046 16.706,13.215 16.985,13.493 18.289,13.493 v5(19.46,14.664)
SWD3_IO: R4.1 U2.N1 | length 41.6
  Top Layer w0.125: v1(16.927,16.649) 17.393,17.115 17.977,17.115 18.628,16.464 U2.N1@19.06,16.464 ; v1(32.665,9.652) 34.978,9.652 35.61,10.284 47.749,10.284 47.89,10.425 R4.1@48.265,10.425
  Bottom Layer w0.125: v1(16.927,16.649) 15.931,15.653 15.931,11.444 17.733,9.642 v1@32.665,9.642
SWD3_RESET: R38.1 U2.AA1 | length 39.8
  Top Layer w0.125: U2.AA1@19.06,14.864 16.789,14.864 16.654,14.729 16.491,14.729 16.233,14.471 16.233,12.658 17.287,11.603 17.891,11.603 18.918,10.576 18.918,9.643 20.702,7.859 35.319,7.859 36.245,8.784 R38.1@48.265,8.784
SWD3_SWO: R37.1 U2.W1 | length 39.5
  Top Layer w0.125: v1(16.463,15.192) 18.703,15.192 18.762,15.25 19.046,15.25 U2.W1@19.06,15.264 ; v1(32.135,10.16) 34.767,10.16 35.399,10.792 47.56,10.792 47.842,11.075 R37.1@48.265,11.075
  Bottom Layer w0.125: v1(16.463,15.192) 16.463,15.161 16.233,14.931 16.233,11.591 17.882,9.942 31.917,9.942 v1(32.135,10.16)
SWDCLK: P15.4 P16.4 U1.26 U6.3 | length 82.3
  Top Layer w0.125: v1(50.619,9.393) 50.66,9.393 50.867,9.6 U6.3@51.379,9.6 ; v1(50.619,12.218) 53.854,15.453 77.632,15.453 80.731,18.552 99.194,18.552 102.723,22.081 102.723,27.476 104.58,29.333 v1(104.58,32.605) ; U1.26@101.64,33.72 101.885,33.72 101.913,33.693 101.938,33.693 102.655,32.975 v1(102.655,32.33)
  Bottom Layer w0.125: v1(50.619,12.218) v1(50.619,9.393) 51.437,8.575 53.438,8.575 55.155,6.858 v1(56.708,6.858) ; v1(102.655,32.33) 102.955,32.63 v1@104.58,32.63
SWDIO: P15.2 P16.2 U1.25 U6.15 | length 78.5
  Top Layer w0.125: v1(51.993,12.851) 54.12,14.978 54.263,14.978 77.825,14.978 80.948,18.102 99.387,18.102 103.157,21.871 103.157,27.305 105.055,29.204 v1(105.055,32.155) ; U6.15@52.004,11.025 v1@52.004,11.746 ; U1.25@101.63,33.33 101.867,33.33 102.105,33.092 v1(102.105,32.68) ; v1(52.003,11.747) v1@52.004,11.746
  Bottom Layer w0.125: v1(51.993,12.851) 52.003,12.84 v1(52.003,11.747) 55.438,8.313 v1(55.438,7.366) ; v1(102.105,32.68) 102.505,33.08 104.777,33.08 105.055,32.802 v1(105.055,32.155)
TWI0_SCL: U2.AF2 U10.14 | length 61.5
  Top Layer w0.15: v1(19.641,49.139) 19.699,49.081 19.699,48.303 U10.14@19.692,48.296
  Mid-Layer 1 w0.125: v1(17.672,12.451) 17.681,12.442 18.041,12.442 v5@19.454,13.855
  Bottom Layer w0.125: v1(17.672,12.451) 17.681,12.442 18.238,12.442 19.567,13.771 19.567,14.273 19.984,14.69 25.285,14.69 25.66,15.065 27.509,15.065 29.078,16.633 29.078,18.53 28.555,19.053 28.555,27.238 29.175,27.858 29.175,28.991 27.324,30.842 27.324,38.714 25.353,40.685 25.353,42.28 28.555,45.482 28.555,48.49 27.373,49.672 24.706,49.672 24.173,49.139 v1(19.641,49.139)
  other v5: 19.46,13.864
TWI0_SDA: U2.AE1 U10.13 | length 65.7
  Top Layer w0.125: v1(17.269,14.385) 17.748,13.906 18.603,13.906 18.761,14.064 U2.AE1@19.059,14.064
  Top Layer w0.15: v1(19.895,49.774) 19.929,49.774 20.192,49.512 U10.13@20.192,48.296
  Bottom Layer w0.125: v1(17.269,14.385) 16.775,13.892 16.775,12.676 17.487,11.965 18.477,11.965 19.508,12.995 24.225,12.995 25.988,14.758 27.634,14.758 29.36,16.484 29.36,18.673 28.854,19.179 28.854,27.122 29.45,27.718 29.45,29.126 27.611,30.965 27.611,38.839 25.639,40.811 25.639,42.135 28.854,45.349 28.854,48.589 27.489,49.953 24.57,49.953 24.041,49.425 20.244,49.425 v1(19.895,49.774)
UART0_CTRL: R13.2 U2.R31 U4.2 | length 48.3
  Top Layer w0.125: U2.R31@25.46,16.064 25.664,16.064 26.56,15.169 27.414,15.169 27.819,15.573 31.481,15.573 35.396,19.488 v1(35.396,22.733) 35.396,39.494 40.474,44.571 U4.2@46.935,44.571 ; R13.2@32.801,22.733 34.232,22.733 v1(34.236,22.737)
  Bottom Layer w0.125: v1(34.236,22.737) 35.392,22.737 v1(35.396,22.733)
UART0_CTS: R55.1 U2.AL9 U4.12 | length 60.3
  Top Layer w0.125: v1(20.279,11.34) 20.279,11.372 20.742,11.834 20.742,11.836 20.86,11.954 U2.AL9@20.86,12.664 ; v1(30.037,16.041) 31.286,16.041 34.929,19.685 34.929,25.908 ; R55.1@32.801,25.908 34.929,25.908 ; U4.12@48.753,44.952 48.753,46.201 48.391,46.562 47.169,46.562 46.597,45.99 46.316,45.99 45.343,45.017 40.259,45.017 34.929,39.687 34.929,25.908
  Bottom Layer w0.125: v1(20.279,11.34) 20.965,12.026 26.753,12.026 28.87,14.143 28.87,14.875 v1(30.037,16.041)
UART0_HWFC: R14.2 U2.AK16 U4.10 | length 62.2
  Top Layer w0.125: v2@25.569,10.832 29.057,14.32 32.183,14.32 36.832,18.97 v1(36.832,24.638) 36.832,25.69 ; R14.2@32.801,24.638 v1(33.717,24.638) ; 36.832,25.696 36.832,38.958 41.125,43.25 45.562,43.25 47.096,41.716 48.324,41.716 49.137,42.529 49.137,43.961 48.945,44.153 48.604,44.153 U4.10@48.585,44.171
  Mid-Layer 1 w0.125: v2(22.26,13.064) 22.27,13.074 22.27,13.282 22.421,13.433 23.23,13.433 23.422,13.241 23.422,13.215 23.423,12.89 23.91,12.402 23.91,10.55 24.268,10.192 24.919,10.192 v2(25.559,10.832)
  Bottom Layer w0.125: v1(33.717,24.638) v1(36.832,24.638)
UART0_RTS: U2.AL5 U4.8 | length 57.4
  Top Layer w0.125: v1(19.34,11.366) 19.797,11.823 19.797,12.23 20.059,12.492 U2.AL5@20.06,12.664 U2.AL5@20.06,12.664 ; v1(27.944,14.381) 28.298,14.734 31.968,14.734 36.326,19.093 36.326,39.126 40.927,43.727 45.579,43.727 47.113,42.193 48.093,42.193 48.36,42.46 U4.8@48.36,43.146
  Bottom Layer w0.125: v1(19.34,11.366) 19.797,11.823 19.797,12.246 20.138,12.587 24.412,12.587 26.205,14.381 v1(27.944,14.381)
UART0_RxD: U2.AL19 U4.4 | length 52
  Top Layer w0.125: U2.AL19@22.86,12.664 22.879,12.645 22.879,12.365 23.353,11.891 23.353,10.326 v2(23.351,10.325) ; v2(26.151,10.827) 29.262,13.938 32.406,13.938 37.302,18.834 37.302,38.764 41.319,42.781 v2(45.23,42.781) ; v2(46.353,43.583) 46.541,43.771 U4.4@46.935,43.771
  Mid-Layer 1 w0.125: v2(23.351,10.325) 23.778,9.898 25.222,9.898 v2(26.151,10.827) ; v2(45.23,42.781) 46.032,43.583 v2(46.353,43.583)
UART0_TxD: U2.U31 U4.16 | length 47
  Top Layer w0.125: U2.U31@25.46,15.664 25.664,15.664 26.484,14.845 27.721,14.845 28.04,15.164 31.726,15.164 35.859,19.297 35.859,39.302 40.723,44.167 v2(45.881,44.167) ; v2(45.881,45.017) 46.46,45.596 U4.16@47.16,45.596
  Mid-Layer 1 w0.125: v2(45.881,44.167) v2(45.881,45.017)
UART1_CTRL: R15.2 U2.AK18 U5.2 | length 52.9
  Top Layer w0.125: v5(22.057,9.74) 22.057,9.39 22.478,8.969 26.75,8.969 29.338,11.557 33.965,11.557 40.075,17.668 v1(40.075,24.003) 40.075,28.688 42.048,30.661 44.736,30.661 v2(44.746,30.652) ; R15.2@32.801,24.003 v1(34.236,24.003) ; v2(45.497,31.734) 45.498,31.735 46.938,31.735 U5.2@46.939,31.736
  Mid-Layer 1 w0.125: v5(22.057,9.74) 22.057,9.985 23.351,11.278 23.351,12.143 22.66,12.834 v2(22.66,13.064) ; v2(44.746,30.652) 45.493,31.399 45.493,31.73 v2(45.497,31.734)
  Bottom Layer w0.125: v1(34.236,24.003) v1(40.075,24.003)
UART1_CTS: R56.1 U2.AL15 U5.12 | length 53.1
  Top Layer w0.125: U2.AL15@22.06,12.664 22.06,12.226 22.336,11.95 22.336,10.756 23.284,9.809 26.423,9.809 29.374,12.76 33.205,12.76 38.687,18.242 v1(38.687,25.273) 38.687,29.263 41.161,31.736 v2(44.987,31.736) ; R56.1@32.801,25.273 v1(34.236,25.273) ; v2(45.485,32.835) 46.353,32.835 47.265,33.747 48.445,33.747 48.804,33.388 48.804,32.18 48.76,32.136 U5.12@48.589,32.136
  Mid-Layer 1 w0.125: v2(44.987,31.736) 44.987,32.337 v2(45.485,32.835)
  Bottom Layer w0.125: v1(34.236,25.273) v1(38.687,25.273)
UART1_HWFC: R16.2 U2.AK20 U5.10 | length 56.4
  Top Layer w0.125: v5(22.54,9.44) 22.736,9.244 26.637,9.244 29.356,11.963 33.717,11.963 39.612,17.859 v1(39.612,23.368) 39.612,28.88 41.747,31.014 44.987,31.014 46.982,29.019 48.293,29.019 49.148,29.874 49.148,31.125 48.955,31.318 48.607,31.318 U5.10@48.589,31.336 ; R16.2@32.801,23.368 33.711,23.368 v1(33.717,23.374)
  Mid-Layer 1 w0.125: v5(22.54,9.44) 22.54,10.078 23.626,11.164 23.626,12.257 23.06,12.822 v2(23.06,13.064)
  Bottom Layer w0.125: v1(33.717,23.374) 39.606,23.374 v1(39.612,23.368)
UART1_RTS: U2.AL13 U5.8 | length 46.1
  Top Layer w0.125: U2.AL13@21.66,12.664 21.66,12.195 22.061,11.793 22.061,10.643 23.17,9.534 26.537,9.534 29.373,12.369 33.469,12.369 39.15,18.051 39.15,29.071 41.45,31.371 45.196,31.371 47.187,29.38 48.104,29.38 48.364,29.64 U5.8@48.364,30.311
UART1_RxD: U2.AL21 U5.4 | length 42.5
  Top Layer w0.125: U2.AL21@23.26,12.664 23.26,12.431 23.658,12.033 23.658,10.575 24.124,10.109 26.335,10.109 29.377,13.151 32.93,13.151 38.221,18.442 38.221,29.456 40.872,32.107 v2(46.304,32.107) ; v2(46.304,30.936) U5.4@46.939,30.936
  Mid-Layer 1 w0.125: v2(46.304,30.936) v2(46.304,32.107)
UART1_TxD: U2.AL23 U5.16 | length 41.1
  Top Layer w0.125: U2.AL23@23.66,12.664 23.671,12.654 23.671,12.457 23.962,12.165 23.962,10.697 24.276,10.384 26.221,10.384 29.377,13.54 32.665,13.54 37.758,18.633 37.758,29.648 40.583,32.473 46.525,32.473 46.814,32.762 U5.16@47.164,32.762
VBUS: C23.2 C49.1 C54.1 J4.5 P30.1 P31.1 P32.1 Q6.3 R5.2 R36.2 SW4.3 TP8.1 U3.5 U10.21 | length 162
  Top Layer w0.125: v1(28.452,8.79) R5.2@28.452,9.367
  Top Layer w0.15: 10.799,50.661 R36.2@10.799,51.726 ; 17.024,54.036 17.878,53.182 18.312,52.749
  Top Layer w0.25: 19.049,54.738 19.242,54.546 ; U3.5@21.474,54.211 21.649,54.036 U3.5@21.649,53.836 ; J4.5@26.976,2.074 v1(27.592,2.69)
  Top Layer w0.27: 19.324,54.811 C49.1@21.649,54.811 U3.5@21.649,54.036
  Top Layer w0.3: C23.2@15.684,45.313 15.684,45.223 15.756,45.295 16.258,45.295 16.56,45.596 U10.21@17.992,45.596
  Top Layer w0.5: 17.064,50.936 v1(17.324,50.936) ; 19.049,54.738 19.049,56.964 20.385,58.3 v1(21.233,58.3)
  Top Layer w0.6: C54.1@11.84,50.661 11.915,50.586 11.915,50.561 12.897,49.58 12.897,45.416 13.777,44.536 15.283,44.536 15.675,44.929 C23.2@15.675,45.304
  Top Layer w0.8: SW4.3@1.021,60.488 3.27,60.488 6.26,57.498 6.26,53.922 9.521,50.661 10.799,50.661 C54.1@11.815,50.661 11.815,44.84 17.555,39.1 29.878,39.1 38.004,47.226 P30.1@42.64,47.226 ; C54.1@11.84,50.661 16.778,50.661 17.324,51.207 v1(17.324,51.686) v1(17.324,52.536) ; v1@17.278,52.582 17.878,53.182 19.242,54.546
  Bottom Layer w0.125: v1(28.452,8.79) 31.24,6.003 31.24,2.69
  Bottom Layer w0.25: v1(27.592,2.69) 31.24,2.69 35.196,2.69 36.314,3.807 37.574,3.807 42.759,8.993 v1(42.759,23.254)
  Bottom Layer w0.5: v1(21.233,58.3) 21.845,58.3 22.106,58.039 TP8.1@23.372,58.039
  Bottom Layer w0.8: v1(42.75,47.75) 42.75,42.146 41.829,41.225 41.829,37.55 42.759,36.62 v1(42.759,36.569) v1(42.759,35.877) 42.759,29.38 41.829,28.45 41.829,24.875 v1(42.759,23.945) v1(42.759,23.254)
  other v1: 42.75,47.116 18.324,50.936 19.324,50.936 17.324,53.286 17.324,54.036 18.324,54.036 19.324,54.036
VBUS_IN: C30.1 C47.2 C48.2 FB2.1 J3.A4 J3.A9 TP16.1 U11.1 | length 4.5
  Top Layer w0.45: FB2.1@11.475,26.85 v1(12.375,26.85)
  Bottom Layer w0.45: v1(12.375,26.85) 13.263,25.962 TP16.1@13.263,23.571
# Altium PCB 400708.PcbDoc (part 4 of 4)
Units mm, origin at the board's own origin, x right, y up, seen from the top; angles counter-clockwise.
Board outline 117 x 63.5 mm, 4 copper layers (Top Layer, Mid-Layer 1, Mid-Layer 2, Bottom Layer), stack 1.556 mm thick; 207 components, 162 nets, 822 pads, 1266 vias.
Unrouted connection lines stored in the file: 43.

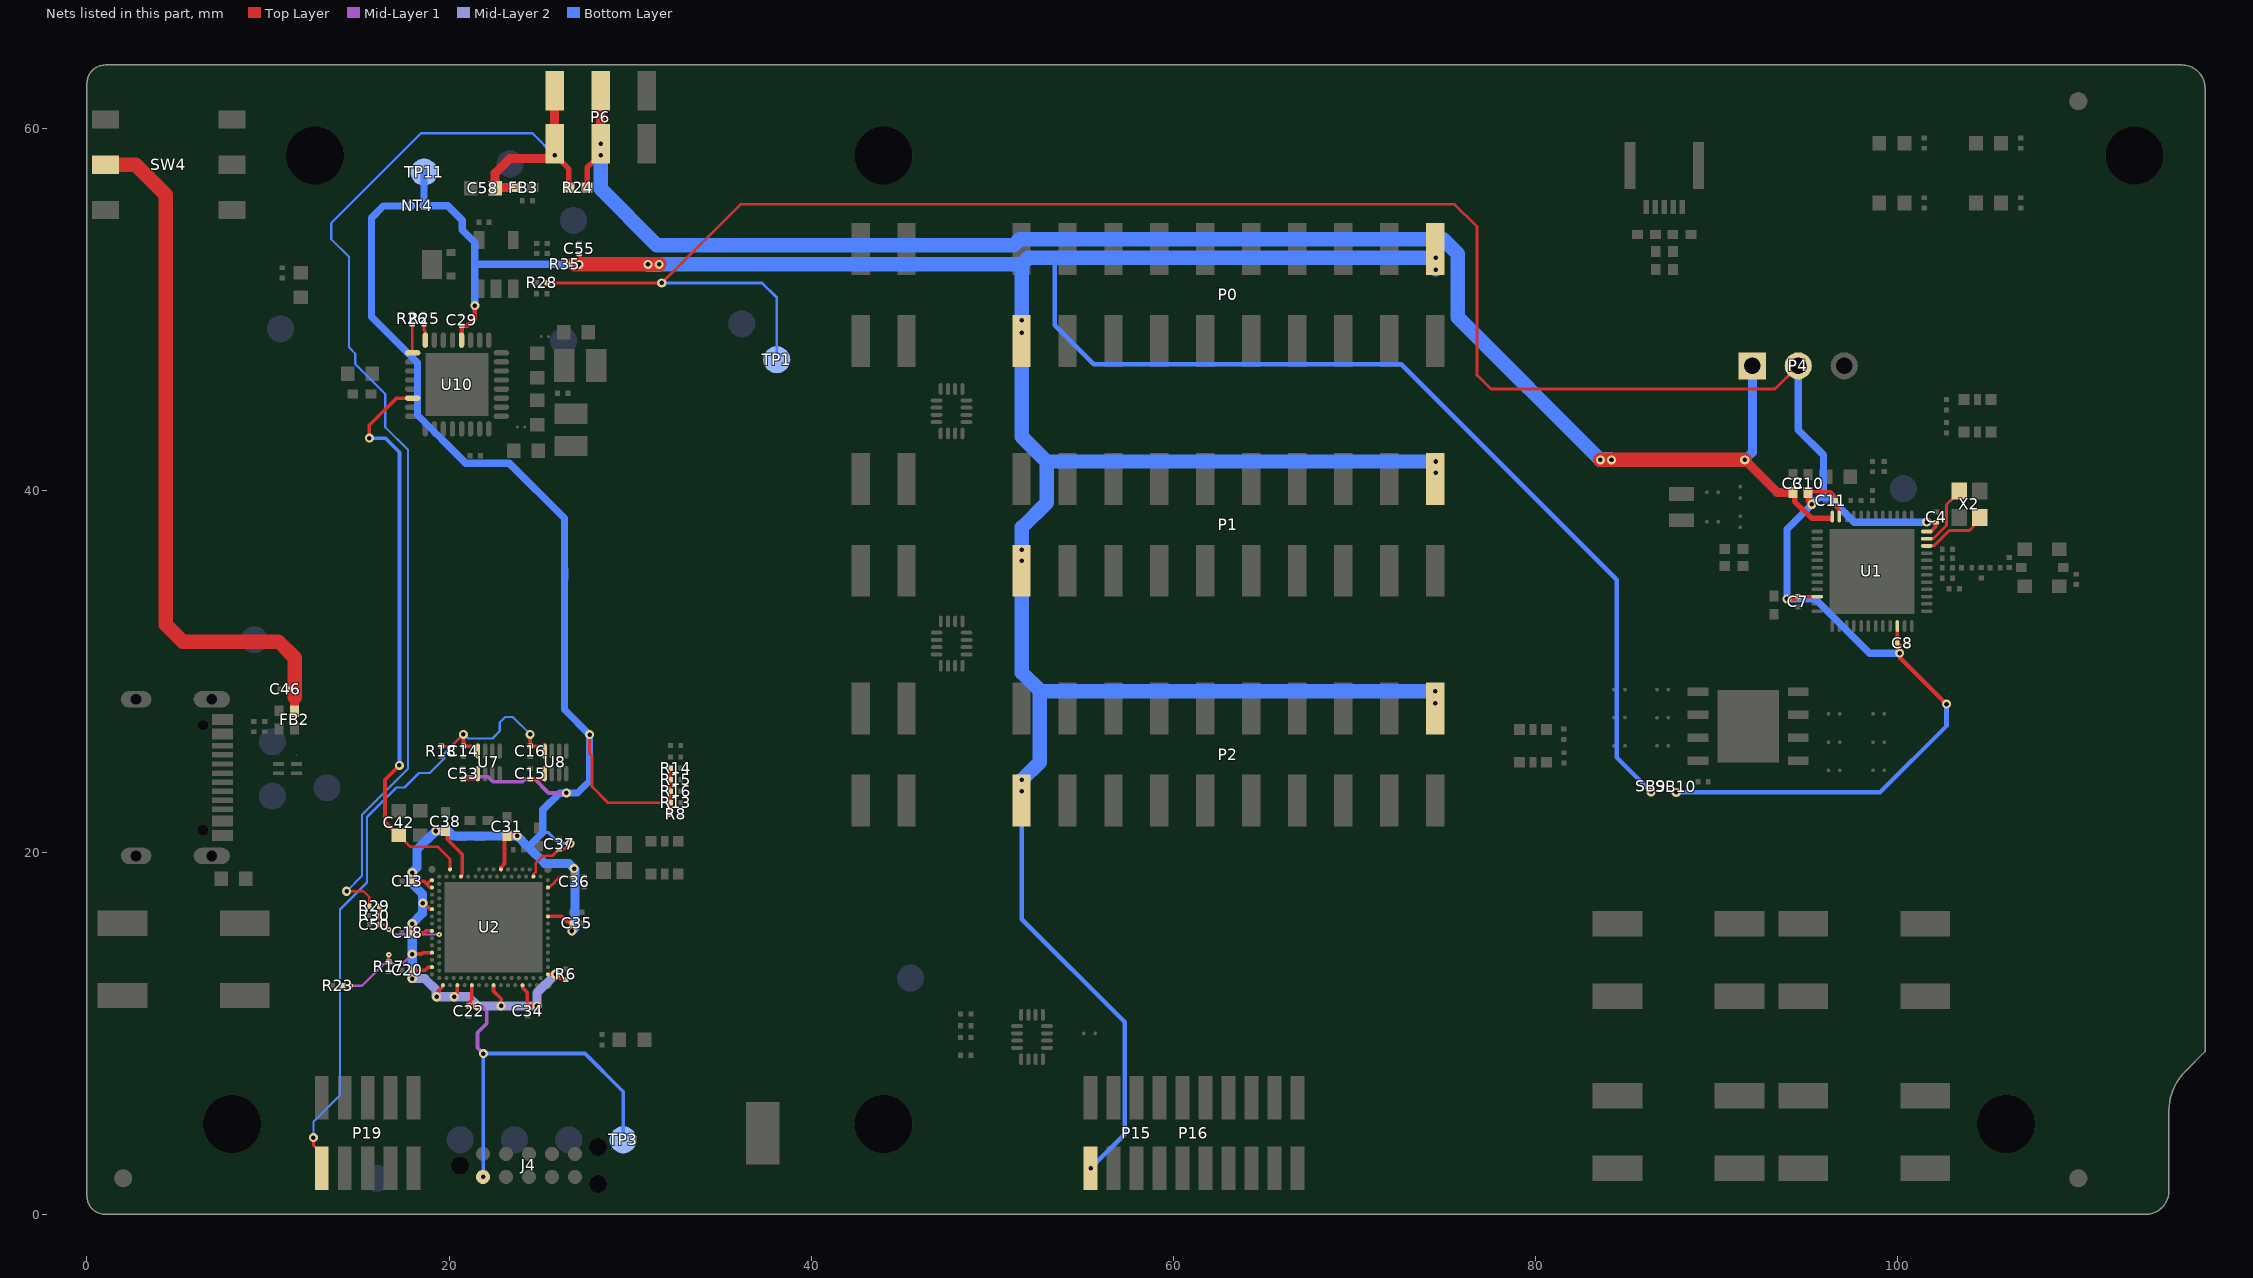
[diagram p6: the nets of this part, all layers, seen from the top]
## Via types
v1: diameter 0.5, hole 0.25, Top Layer to Bottom Layer, tented both sides, 1159 vias
v2: diameter 0.3, hole 0.1, Top Layer to Mid-Layer 1, tented top, 61 vias
v3: diameter 0.61, hole 0.305, Top Layer to Bottom Layer, tented both sides, 28 vias
v4: diameter 0.61, hole 0.305, Top Layer to Bottom Layer, 9 vias
v5: diameter 0.3, hole 0.1, Top Layer to Mid-Layer 1, tented both sides, 9 vias

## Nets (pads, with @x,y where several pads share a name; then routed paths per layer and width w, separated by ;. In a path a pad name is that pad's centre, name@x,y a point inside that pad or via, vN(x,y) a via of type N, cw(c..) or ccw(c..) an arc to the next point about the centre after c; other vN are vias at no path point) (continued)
VBUS_IN': C46.2 FB2.2 SW4.2 | length 38.6
  Top Layer w0.5: FB2.2@11.475,27.8 11.475,28.575
  Top Layer w0.8: SW4.2@1.021,57.988 2.687,57.988 4.349,56.326 4.349,32.59 5.288,31.65 10.579,31.65 11.475,30.754 11.475,28.575
VBUSOUT: C42.1 U2.A5 U10.22 | length 31.5
  Top Layer w0.15: C42.1@17.226,20.947 17.866,20.306 19.39,20.306 20.06,19.637 U2.A5@20.06,19.064
  Top Layer w0.2: v1(15.601,42.89) 15.601,43.589 17.097,45.086 17.981,45.086 U10.22@17.992,45.096 ; C42.1@17.226,20.947 C42.1@17.231,20.952 17.206,20.952 16.465,21.694 16.465,24.011 v1(17.264,24.81)
  Bottom Layer w0.2: v1(15.601,42.89) 16.478,42.89 17.264,42.104 v1(17.264,24.81)
VDD_DBGR: C13.1 C15.2 C18.1 C20.1 C22.1 C31.1 C34.1 C35.1 C36.1 C37.1 C38.2 C53.2 J4.1 NT4.1 R6.2 R8.2 R13.1 R14.1 R15.1 R16.1 R17.1 R23.2 TP3.1 U2.A19 U2.AC1 U2.AG1 U2.AJ31 U2.AL3 U2.AL7 U2.AL11 U2.AL17 U2.AL25 U2.B8 U2.B28 U2.C1 U2.E1 U2.E31 U2.L1 U2.N31 U2.U1 U7.1 U8.1 | length 151
  Top Layer w0.125: R23.2@14.139,12.634 14.544,12.634 v2(14.546,12.631) ; R17.1@16.668,13.981 16.672,13.986 16.672,14.34 v2(16.677,14.344)
  Top Layer w0.15: U2.B28@24.66,18.664 24.675,18.679 24.675,18.801 24.798,18.925 24.798,19.204 24.798,19.427 25.185,19.815 25.722,19.815 26.081,20.174 C37.1@26.096,20.174 26.11,20.188 26.383,20.188 v1(26.685,20.49) ; U2.E31@25.443,18.079 25.562,18.079 25.824,18.341 25.824,18.364 26.102,18.642 26.125,18.642 26.134,18.651 26.899,18.651 C36.1@26.909,18.661 ; v1(25.893,13.271) 26.173,12.991 26.454,12.991 R6.2@26.46,12.986 ; v1(27.765,26.506) 27.765,25.471 27.896,25.339 27.896,23.636 28.788,22.744 R13.1@32.231,22.744 ; R8.2@32.231,22.098 R13.1@32.231,22.733 R16.1@32.231,23.368 R15.1@32.231,24.003 R14.1@32.231,24.638
  Top Layer w0.187: v1(19.269,21.184) 19.777,21.184 C38.2@19.797,21.203 19.901,21.099 19.901,20.735 20.735,19.901 20.735,18.75 20.66,18.675 U2.B8@20.66,18.664 ; U2.N31@25.46,16.464 26.236,16.464 26.572,16.128 C35.1@26.691,16.128
  Top Layer w0.2: v1(17.968,13.03) 17.968,13.471 17.98,13.471 18.009,13.499 18.682,13.499 18.842,13.66 19.055,13.66 U2.AG1@19.06,13.664 ; v1(17.968,14.381) 17.976,14.388 18.481,14.388 18.558,14.464 U2.AC1@19.06,14.464 ; v1(17.968,16.065) 17.971,16.062 17.971,15.575 C18.1@17.974,15.573 18.625,15.573 18.716,15.664 U2.U1@19.06,15.664 ; v1(17.968,18.884) 17.971,18.881 17.971,18.404 C13.1@17.974,18.401 18.624,18.401 18.776,18.249 ; v1(18.553,17.194) 18.618,17.194 18.943,16.869 19.055,16.869 U2.L1@19.06,16.864 ; U2.E1@19.06,18.064 18.961,18.064 18.776,18.249 ; U2.C1@19.06,18.464 19.055,18.46 18.986,18.46 18.776,18.249 ; v1(19.314,12.026) 19.372,12.083 19.372,12.296 19.655,12.58 19.655,12.66 U2.AL3@19.66,12.664 ; v1(20.279,12.026) 20.279,12.107 20.46,12.288 U2.AL7@20.46,12.664 ; v2(20.798,24.064) U7.1@21.591,24.064 ; C22.1@21.092,11.524 21.127,11.559 21.13,11.559 21.13,11.759 21.26,11.889 U2.AL11@21.26,12.664 ; C22.1@21.101,11.521 21.572,11.521 v1(21.575,11.518) ; U2.AL17@22.46,12.664 22.46,12.334 22.878,11.916 v1(22.878,11.518) ; U2.AL25@24.06,12.664 24.065,12.66 24.065,12.514 24.318,12.261 24.318,11.549 24.346,11.521 24.856,11.521 v1(24.86,11.525) ; v2(24.481,24.064) 25.288,24.064 U8.1@25.303,24.049 ; U8.1@25.255,24.181 25.278,24.204 U8.1@25.278,24.349 ; U2.AJ31@25.46,13.264 25.887,13.264 v1(25.893,13.271) ; C35.1@26.691,16.128 26.748,16.128 26.783,16.093 C35.1@26.783,16.078 v1(26.782,15.659)
  Top Layer w0.203: v1(26.907,19.101) 26.909,19.1 C36.1@26.909,18.661
  Top Layer w0.225: U2.A19@22.86,19.064 22.86,19.179 23.073,19.392 23.073,20.848 C31.1@23.15,20.924 ; C31.1@23.2,20.916 v1(23.759,20.916)
  Mid-Layer 1 w0.125: v2(14.546,12.631) 15.191,12.631 16.418,13.858 16.677,13.858 ; v2@16.701,14.319 v2(16.677,14.344) 16.677,13.858 ; v1(17.968,14.381) 17.445,13.858 16.677,13.858
  Mid-Layer 1 w0.2: v2(20.798,24.064) 20.825,24.064 20.944,24.183 22.157,24.183 22.435,23.904 24.064,23.904 24.224,24.064 24.72,24.064 25.501,23.283 26.48,23.283 v1(26.487,23.29) ; v1(21.575,11.518) 21.632,11.461 21.849,11.461 22.09,11.22 22.09,10.555 21.575,10.039 21.575,9.207 v1(21.893,8.889)
  Mid-Layer 2 w0.5: v1(17.968,13.03) 18.666,13.03 19.295,12.401 19.295,12.045 v1(19.314,12.026) v1(20.279,12.026) 21.067,12.026 v1(21.575,11.518) v1(22.878,11.518) 22.885,11.525 v1(24.86,11.525) 24.86,12.238 v1(25.893,13.271)
  Bottom Layer w0.15: 25.182,21.098 25.482,21.098 26.09,20.49 v1(26.685,20.49)
  Bottom Layer w0.2: v1@21.893,2.31 v1(21.893,8.889) 27.513,8.889 29.62,6.782 TP3.1@29.62,4.115
  Bottom Layer w0.4: NT4.1@17.86,55.716 16.378,55.716 15.725,55.062 15.725,49.575 18.256,47.044 18.256,44.169 20.925,41.5 23.331,41.5 26.375,38.456 26.375,35.652 26.392,35.636 26.392,35.138 26.375,35.122 26.375,27.896 v1(27.765,26.506) 27.765,23.95 27.097,23.283 26.495,23.283 v1(26.487,23.29) 26.471,23.274 26.102,23.274 25.182,22.354 25.182,21.098 24.379,20.296 ; v1@17.968,18.911 v1(17.968,18.884) v1@17.987,18.865 ; v1@18.533,17.213 v1(18.553,17.194)
  Bottom Layer w0.5: v1(17.968,13.03) v1(17.968,14.381) v1(17.968,16.065) 18.533,16.63 18.533,17.175 v1(18.553,17.194) ; v1@17.968,18.911 18.222,19.165 18.222,20.137 v1(19.269,21.184) 19.955,21.184 20.223,20.916 v1(23.759,20.916) 24.379,20.296 25.285,19.39 26.619,19.39 26.949,19.06 26.949,15.825 v1(26.782,15.659) ; v1@17.987,18.865 17.987,18.256 18.533,17.71 v1@18.533,17.213
  other v1: 21.878,2.074
VDD_nRF: C4.1 C7.1 C8.1 C10.2 C11.1 P4.2 R28.1 SB10.1 TP1.1 U1.10 U1.22 U1.36 U1.47 | length 148.9
  Top Layer w0.15: R28.1@25.409,51.461 v1(31.752,51.461) 36.091,55.8 43.924,55.8 ccw(c44.004,58.5) 44.084,55.8 75.554,55.8 76.789,54.565 76.789,46.366 77.555,45.6 93.255,45.6 P4.2@94.535,46.88
  Top Layer w0.152: 87.363,23.485 87.513,23.335 87.774,23.335 v1(87.794,23.315)
  Top Layer w0.2: C7.1@94.503,34.134 C7.1@94.518,34.134 ; C7.1@94.523,34.13 U1.10@95.58,34.13 ; C10.2@95.077,39.877 95.12,39.92 96.309,39.92 96.572,39.658 96.572,39.472 C11.1@96.607,39.437 ; C11.1@96.627,39.443 96.627,39.068 96.805,38.889 U1.47@96.805,38.555 ; C8.1@99.999,31.568 100.034,31.533 C8.1@100.034,31.518 ; C8.1@100.005,31.568 U1.22@100.005,32.505 ; U1.36@101.63,37.73 101.855,37.73 101.855,37.732 102.114,37.99 C4.1@102.114,38.178 ; v1(101.63,38.244) 101.639,38.235 102.126,38.235 C4.1@102.149,38.213
  Top Layer w0.25: v1(93.909,34.002) 93.931,34.024 94.393,34.024 C7.1@94.503,34.134 ; C8.1@100.034,31.518 100.132,31.42 v1(100.132,31.005) 100.18,30.957 100.18,30.734 102.723,28.191 v1(102.723,28.189)
  Top Layer w0.4: C10.2@95.077,39.877 95.127,39.827 95.127,39.414 95.28,39.261 v1(95.28,39.234)
  Bottom Layer w0.15: v1(31.752,51.461) 37.296,51.461 38.104,50.653 TP1.1@38.104,47.219
  Bottom Layer w0.25: v1(87.794,23.315) 99.05,23.315 102.723,26.988 v1(102.723,28.189)
  Bottom Layer w0.3: 93.909,35.496 93.921,35.484
  Bottom Layer w0.4: v1(93.909,34.002) 95.473,34.002 98.47,31.005 v1(100.132,31.005) ; v1@93.909,34.048 93.909,35.496 93.909,37.848 95.667,39.606 95.935,39.606 ; P4.2@94.535,46.88 94.535,43.338 95.935,41.938 95.935,39.606 ; v1@101.603,38.244 97.62,38.244 96.258,39.606 95.935,39.606
VDD_SWD0: C14.1 C16.1 P19.1 R18.2 U7.8 U8.8 | length 37.6
  Top Layer w0.125: R18.2@19.573,25.87 20.144,25.87 v1(20.798,26.524)
  Top Layer w0.15: v1(12.513,4.246) 12.513,3.821 12.822,3.512 12.822,2.692 P19.1@12.964,2.55
  Top Layer w0.2: v1(20.798,26.524) C14.1@20.798,25.87 U7.8@21.591,25.87 ; v1(24.481,26.524) C16.1@24.481,25.87 25.274,25.87 U8.8@25.303,25.899
  Bottom Layer w0.125: v1(12.513,4.246) 12.513,5.118 13.982,6.588 13.982,16.841 15.474,18.332 15.474,21.962 17.103,23.591 17.538,23.591 18.34,24.393 18.93,24.393 19.745,25.209 19.745,25.471 v1(20.798,26.524) 20.83,26.524 21.059,26.295 22.396,26.295 22.802,26.701 22.802,27.177 23.104,27.479 23.526,27.479 v1(24.481,26.524)
VDDIO: C29.1 C55.1 NT4.2 P0.1 P0.20 P1.1 P1.20 P2.1 P2.20 P15.1 P16.1 R35.2 SB9.1 TP11.1 U10.12 | length 219.5
  Top Layer w0.25: U10.12@20.692,48.296 C29.1@20.692,49.101 ; C29.1@20.699,49.101 20.724,49.101 21.014,49.101 21.424,49.511 v1(21.424,50.211) ; v1(27.187,52.486) C55.1@27.187,53.076
  Top Layer w0.8: 26.929,52.486 v1(27.187,52.486) v1(30.992,52.486) v1(31.609,52.486)
  Bottom Layer w0.25: v1(51.649,23.381) 51.644,23.377 51.644,16.315 57.329,10.63 57.329,4.441 v1(55.438,2.55) ; 53.469,52.845 53.469,49.118 55.612,46.975 72.594,46.975 84.5,35.07 84.5,25.245 v1(86.405,23.34)
  Bottom Layer w0.4: TP11.1@18.622,57.582 NT4.2@18.622,55.733 18.631,55.724 19.929,55.724 20.735,54.919 20.735,54.384 21.424,53.695 21.424,52.486 ; v1(21.424,50.211) 21.424,52.486 ; v1(27.187,52.486) 21.424,52.486
  Bottom Layer w0.8: v1(30.992,52.486) v1(31.609,52.486) 32.226,52.486 51.629,52.486 ; v1(51.649,23.381) v1(51.649,24.006) 52.625,24.982 52.625,28.871 ; v1(51.65,36.1) 51.649,29.933 52.677,28.905 ; v1(51.65,36.1) v1(51.65,36.725) 51.65,37.95 53.025,39.325 53.025,41.613 ; 52.709,28.905 v1(74.484,28.905) ; 52.904,41.686 51.629,42.961 v1(51.629,48.712) v1(51.629,49.403) 51.629,52.486 ; 53.055,41.595 v1(74.504,41.595) v1(74.504,40.97) ; v1(74.485,28.243) v1(74.484,28.905) ; v1@74.51,52.21 v1(74.51,52.845) 53.469,52.845 51.988,52.845 51.629,52.486
  other v1: 74.5,52.175
VDDM: C58.1 FB3.2 P6.3 R24.2 R29.2 | length 67.5
  Top Layer w0.125: v1(14.344,17.856) 15.277,17.856 15.594,17.539 R29.2@15.594,17.018
  Top Layer w0.3: v1(25.832,58.5) 25.888,58.5 26.192,58.196 26.192,58.183 26.625,57.75 R24.2@26.625,56.725
  Top Layer w0.5: C58.1@22.511,56.733 22.552,56.775 22.552,57.527 23.35,58.325 25.572,58.325 P6.3@25.832,58.585 ; C58.1@22.617,56.759 22.651,56.725 FB3.2@23.667,56.725 ; v1(25.832,58.5) P6.3@25.832,58.585 ; P6.3@25.832,59.141 P6.3@25.832,58.585 ; P6.3@25.832,59.781 P6.3@25.832,62.071
  Bottom Layer w0.125: v1(14.344,17.856) 15.199,18.711 15.199,22.086 17.733,24.62 17.733,42.242 16.483,43.492 16.483,45.327 14.825,46.985 14.825,47.55 14.475,47.9 14.475,52.9 13.5,53.875 13.5,54.775 17.487,58.762 18.45,59.725 24.607,59.725 v1(25.832,58.5)
VDDM_nRF: C3.2 P4.1 P6.2 R24.1 U1.48 | length 92
  Top Layer w0.3: R24.1@27.625,56.725 27.625,57.825 27.996,58.196 28.068,58.196 v1(28.372,58.5) v1(28.372,59.141) ; C3.2@94.339,39.752 94.339,39.398 95.281,38.456 U1.48@96.355,38.456
  Top Layer w0.5: v1(28.372,59.141) P6.2@28.372,62.071 ; v1(91.577,41.68) 93.367,39.89 C3.2@94.239,39.89
  Top Layer w0.8: v1(83.607,41.68) v1(84.216,41.68) v1(91.577,41.68)
  Bottom Layer w0.5: v1(91.577,41.68) 91.995,42.098 P4.1@91.995,46.88
  Bottom Layer w0.8: v1(28.372,58.5) 28.372,56.662 31.484,53.55 51.2,53.55 51.525,53.875 74.922,53.875 75.728,53.069 75.728,49.559 v1(83.607,41.68) v1(84.216,41.68) ; v1@28.372,58.527 v1(28.372,59.141)
VMEAS_CH1: C50.1 R29.1 R30.2 U2.V2 | length 4.6
  Top Layer w0.125: R29.1@16.164,17.018 R30.2@16.164,16.51 C50.1@16.164,16.002 16.418,16.002 v5(16.677,15.744) v5@16.677,15.791
  Mid-Layer 1 w0.125: v5(16.677,15.744) 16.956,15.464 v5(19.46,15.464)
VSET1: R26.1 U10.17 | length 1.9
  Top Layer w0.15: U10.17@17.742,47.665 17.811,47.596 U10.17@17.992,47.596 17.974,47.614 R26.1@17.974,49.183
VSET2: R25.1 U10.16 | length 0.9
  Top Layer w0.15: R25.1@18.619,49.183 18.619,48.846 18.678,48.787 18.678,48.31 U10.16@18.692,48.296
XC1: U1.34 X2.1 | length 3.6
  Top Layer w0.15: U1.34@101.691,36.94 102.028,36.94 102.875,37.786 103.993,37.786 104.218,38.011 104.218,38.159 X2.1@104.568,38.509
XC2: U1.35 X2.3 | length 3.6
  Top Layer w0.15: U1.35@101.63,37.33 101.64,37.34 102.004,37.34 102.723,38.058 102.723,39.209 103.068,39.554 103.068,39.609 X2.3@103.418,39.959
pads on no net: Fid1.0 Fid2.0 Fid3.0 J3. J3.0 J3.A8 J3.B8 J4.0 J4.6 J4.7 J4.8 J4.9 J7.0 J7.1 J7.3 J7.5 P0.8 P0.9 P0.10 P0.11 P0.12 P0.13 P0.14 P0.15 P0.16 P0.17 P0.18 P1.18 P2.14 P2.15 P2.16 P2.17 P2.18 P15.7 P15.8 P16.7 P16.8 P16.11 P16.13 P19.7 P19.8 P19.9 P30.3 P31.3 P32.3 SW4.1 SW4.6 U2. U2.A1 U2.A21 U2.A31 U2.AD2 U2.AE31 U2.AG31 U2.AH2 U2.AJ1 U2.AK2 U2.AK4 U2.AK6 U2.AK8 U2.AK10 U2.AK12 U2.AK22 U2.AK24 U2.AK26 U2.AK28 U2.AK30 U2.AL1 U2.AL31 U2.B10 U2.B14 U2.D2 U2.F2 U2.J1 U2.K2 U2.M2 U2.P2 U2.T2 U2.Y2 U4.1 U4.5 U4.9 U4.13 U5.1 U5.5 U5.9 U5.13 U6.1 U6.5 U6.9 U6.13 U10.7 U10.9 U10.10 U10.11 U10.15 U10.18 U10.19 U10.25 U10.26 U10.27 U10.28 U10.29 U11.4

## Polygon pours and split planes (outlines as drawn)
GND on Top Layer "GND_island" (solid, pour order 4): 103.874,35.423 103.874,34.914 104.306,34.482 104.991,34.482 105.397,34.888 105.397,35.422
GND on Top Layer "Top_Layer-GND" (solid, remove dead copper, pour order 0): 0.002,0.009 0.002,63.509 117.004,63.509 117.004,0.009
GND on Mid-Layer 1 "Mid_Layer1-GND" (solid, remove dead copper, pour order 1): 0.029,0 0.029,63.22 117.004,63.22 117.004,0
GND on Bottom Layer "Bottom_Layer-GND" (solid, remove dead copper, pour order 3): 0.029,0 0.029,63.5 117.004,63.5 117.004,0
GND on Mid-Layer 2 "Mid_Layer2-GND" (solid, remove dead copper, pour order 2): 0.029,0 0.029,63.5 117.004,63.5 117.004,0

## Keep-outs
Keep-Out Layer:
  circle w0.152: c12.604,58.5 r2.4
  circle w0.152: c113.104,58.5 r2.4
  circle w0.152: c113.104,58.5 r2.4
  circle w0.152: c106.004,5 r2.4
  circle w0.152: c44.004,5 r2.4
  circle w0.152: c44.004,58.5 r2.4
  circle w0.152: c8.004,5 r2.4

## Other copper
Top Layer:
  rectangle net VBUS: 16.378,50.261 19.674,54.936
  rectangle net GND: 6.919,27.025 8.804,27.85
  rectangle net GND: 109.224,34.036 110.038,34.931
  rectangle net GND: 6.891,20.422 8.776,21.247
  rectangle net ANT: 115.025,16.986 116.295,17.748
  rectangle net NetC51_2: 24.634,52.286 24.974,52.686
  rectangle net NetR31_2: 25.274,52.286 26.249,52.686
  pour cut-out: 103.874,35.423 103.874,34.914 104.306,34.482 104.991,34.482 105.398,34.889 105.397,34.889 105.397,35.423 105.547,35.423 105.547,34.802 105.065,34.32 104.227,34.32 103.719,34.828 103.719,35.423
  region net P5V0: 15.317,45.946 15.317,46.871 15.317,48.011 17.199,48.011 17.199,46.501 17.454,46.246 18.042,46.246 18.042,45.946
  region net P5V0: 23.603,45.459 24.467,44.596 25.524,44.596 25.524,46.596 24.467,46.596 23.604,45.733
  region net NetC59_1: 7.874,19.8 7.874,18.1 5.874,18.1 5.874,19.8
  region net VBUS_IN: 11.725,27.175 11.725,26.525 10.879,26.525 10.879,25.283 10.101,25.283 9.725,25.659 9.725,26.15 9.641,26.234 6.876,26.234 6.719,26.077 6.719,22.178 6.864,22.034 8.059,22.034 8.059,21.434 6.873,21.434 5.95,22.357 5.95,25.875 6.909,26.834 9.937,26.834 10.15,26.621 10.15,25.855 10.522,25.483 10.679,25.483 10.679,25.604 10.35,25.933 10.35,27.175
  region net NetL2_1: 102.387,35.879 101.998,35.829 101.998,35.63 102.387,35.579
  pour cut-out: 99.09,39.615 98.278,39.615 98.278,41.467 99.09,41.467
  pour cut-out: 24.604,51.4 24.604,52.4 24.704,52.4 24.704,51.4
  pour cut-out: 96.858,41.292 96.649,41.292 96.649,41.179 96.858,41.179
  pour cut-out: 105.311,40.732 105.311,37.477 102.443,37.477 102.443,40.732
  pour cut-out: 102.811,36.895 102.811,36.591 102.923,36.591 102.923,36.895
  region net PVSS2: 22.892,46.446 23.45,46.446 24.2,47.196 25.524,47.196 25.524,47.91 25.7,48.086 26.917,48.086 26.917,49.146 24.742,49.146 24.392,48.796 24.392,47.873 23.264,46.746 22.892,46.746
  region net NetC27_2: 24.399,42.586 25.69,42.586 25.817,42.713 25.817,43.016 27.652,43.016 27.652,41.589 27.474,41.411 24.399,41.411
  pour cut-out: 25.839,43.656 25.839,43.016 27.809,43.016 27.809,43.656
  pour cut-out: 26.929,45.827 27.569,45.827 27.569,47.797 26.929,47.797
  region net P3V3: 27.542,45.961 27.542,47.669 27.117,48.094 27.117,49.146 28.524,49.146 28.692,48.979 28.692,45.961
  region net PVSS1: 22.892,44.446 23.264,44.446 23.499,44.211 23.499,43.936 23.199,43.636 23.199,41.786 24.249,41.786 24.249,42.711 24.299,42.761 25.524,42.761 25.524,43.996 24.164,43.996 23.414,44.746 22.892,44.746
  pour cut-out: 22.737,54.811 25.599,54.811 26.274,54.136 26.274,52.486 22.737,52.486
Mid-Layer 1:
  pour cut-out: 110.038,37.125 106.927,37.125 106.302,36.5 102.775,36.5 102.775,35.324 103.7,35.324 103.7,34.95 106.302,34.95 106.927,34.325 110.038,34.325
  pour cut-out: 103.719,35.318 103.719,34.828 104.227,34.32 105.065,34.32 105.547,34.802 105.547,35.318
  pour cut-out: 89.122,39.161 89.122,40.616 90.485,40.616 90.485,39.161
  pour cut-out: 96.297,25.389 96.297,26.844 96.752,26.844 96.752,25.389
  pour cut-out: 96.298,26.939 96.298,28.394 96.753,28.394 96.753,26.939
  pour cut-out: 86.816,25.164 86.816,26.619 87.271,26.619 87.271,25.164
  pour cut-out: 86.816,26.714 86.816,28.169 87.271,28.169 87.271,26.714
  pour cut-out: 86.817,28.264 86.817,29.719 87.272,29.719 87.272,28.264
  pour cut-out: 89.122,37.535 89.122,38.991 90.485,38.991 90.485,37.535
  pour cut-out: 85.805,23.848 87.005,23.848 87.005,23.392 85.805,23.392
  pour cut-out: 96.297,23.839 96.297,25.294 96.752,25.294 96.752,23.839
  pour cut-out: 55.167,9.398 55.167,10.598 55.622,10.598 55.622,9.398
  pour cut-out: 12.196,10.489 12.196,11.689 12.688,11.689 12.688,10.489
Mid-Layer 2:
  rectangle net VBUS: 16.378,50.261 19.674,54.936
  pour cut-out: 110.038,37.125 106.927,37.125 106.302,36.5 102.775,36.5 102.775,35.324 103.7,35.324 103.7,34.95 106.302,34.95 106.927,34.325 110.038,34.325
  pour cut-out: 103.719,35.318 103.719,34.828 104.227,34.32 105.065,34.32 105.547,34.802 105.547,35.318
  region net P5V0: 25.026,45.125 25.278,45.415 25.278,46.422 22.985,48.715 15.74,48.715 15.55,48.525 15.55,46.2 15.8,45.95 17.454,45.95 19.029,47.525 21.821,47.525 23.629,45.717 23.629,45.496 24.001,45.125
Bottom Layer:
  rectangle net VBUS: 16.378,50.261 19.674,54.936
  pour cut-out: 20.072,29.999 cw(c19.12,29.999) 19.12,29.047 cw(c19.12,29.995) 18.172,29.995 18.172,30.006 cw(c19.113,30.006) 19.113,30.947 19.124,30.947 cw(c19.124,29.999)
  pour cut-out: 10.085,12.152 cw(c9.133,12.152) 9.133,11.2 cw(c9.133,12.149) 8.185,12.149 8.185,12.159 cw(c9.126,12.159) 9.126,13.1 9.137,13.1 cw(c9.137,12.152)
  pour cut-out: 23.027,54.815 cw(c22.075,54.815) 22.075,53.863 cw(c22.075,54.811) 21.127,54.811 21.127,54.822 cw(c22.068,54.822) 22.068,55.763 22.079,55.763 cw(c22.079,54.815)
  pour cut-out: 15.483,54.307 cw(c14.531,54.307) 14.531,53.355 cw(c14.531,54.303) 13.583,54.303 13.583,54.314 cw(c14.524,54.314) 14.524,55.255 14.535,55.255 cw(c14.535,54.307)
  pour cut-out: 32.984,37.568 cw(c32.032,37.568) 32.032,36.617 cw(c32.032,37.565) 31.084,37.565 31.084,37.576 cw(c32.025,37.576) 32.025,38.517 32.036,38.517 cw(c32.036,37.568)
  pour cut-out: 38.368,38.713 cw(c37.417,38.713) 37.417,37.761 cw(c37.417,38.71) 36.469,38.71 36.469,38.72 cw(c37.41,38.72) 37.41,39.661 37.42,39.661 cw(c37.42,38.713)
  pour cut-out: 39.869,42.397 cw(c38.918,42.397) 38.918,41.445 cw(c38.918,42.393) 37.969,42.393 37.969,42.404 cw(c38.911,42.404) 38.911,43.345 38.921,43.345 cw(c38.921,42.397)
  pour cut-out: 27.284,48.262 cw(c26.332,48.262) 26.332,47.31 cw(c26.332,48.258) 25.384,48.258 25.384,48.269 cw(c26.325,48.269) 26.325,49.21 26.336,49.21 cw(c26.336,48.262)
  pour cut-out: 16.397,44.858 cw(c15.446,44.858) 15.446,43.906 cw(c15.446,44.854) 14.498,44.854 14.498,44.865 cw(c15.439,44.865) 15.439,45.806 15.449,45.806 cw(c15.449,44.858)
  pour cut-out: 14.213,38.847 cw(c13.261,38.847) 13.261,37.895 cw(c13.261,38.843) 12.313,38.843 12.313,38.854 cw(c13.254,38.854) 13.254,39.795 13.265,39.795 cw(c13.265,38.847)
  pour cut-out: 11.19,41.354 cw(c10.239,41.354) 10.239,40.403 cw(c10.239,41.351) 9.291,41.351 9.291,41.362 cw(c10.232,41.362) 10.232,42.303 10.242,42.303 cw(c10.242,41.354)
  pour cut-out: 11.19,38.354 cw(c10.239,38.354) 10.239,37.403 cw(c10.239,38.351) 9.291,38.351 9.291,38.362 cw(c10.232,38.362) 10.232,39.303 10.242,39.303 cw(c10.242,38.354)
  pour cut-out: 16.982,27.612 cw(c16.03,27.612) 16.03,26.66 cw(c16.03,27.608) 15.082,27.608 15.082,27.619 cw(c16.023,27.619) 16.023,28.56 16.034,28.56 cw(c16.034,27.612)
  pour cut-out: 22.747,27.434 cw(c21.796,27.434) 21.796,26.482 cw(c21.796,27.43) 20.848,27.43 20.848,27.441 cw(c21.789,27.441) 21.789,28.382 21.799,28.382 cw(c21.799,27.434)
  pour cut-out: 25.747,28.424 cw(c24.796,28.424) 24.796,27.473 cw(c24.796,28.421) 23.848,28.421 23.848,28.432 cw(c24.789,28.432) 24.789,29.373 24.799,29.373 cw(c24.799,28.424)
  pour cut-out: 28.747,28.424 cw(c27.796,28.424) 27.796,27.473 cw(c27.796,28.421) 26.848,28.421 26.848,28.432 cw(c27.789,28.432) 27.789,29.373 27.799,29.373 cw(c27.799,28.424)
  pour cut-out: 38.165,26.748 cw(c37.213,26.748) 37.213,25.796 cw(c37.213,26.744) 36.265,26.744 36.265,26.755 cw(c37.206,26.755) 37.206,27.696 37.217,27.696 cw(c37.217,26.748)
  pour cut-out: 38.165,21.748 cw(c37.213,21.748) 37.213,20.796 cw(c37.213,21.744) 36.265,21.744 36.265,21.755 cw(c37.206,21.755) 37.206,22.696 37.217,22.696 cw(c37.217,21.748)
  pour cut-out: 38.165,16.748 cw(c37.213,16.748) 37.213,15.796 cw(c37.213,16.744) 36.265,16.744 36.265,16.755 cw(c37.206,16.755) 37.206,17.696 37.217,17.696 cw(c37.217,16.748)
  pour cut-out: 38.165,11.748 cw(c37.213,11.748) 37.213,10.796 cw(c37.213,11.744) 36.265,11.744 36.265,11.755 cw(c37.206,11.755) 37.206,12.696 37.217,12.696 cw(c37.217,11.748)
  pour cut-out: 20.458,41.347 20.458,41.035 20.627,41.035 20.627,41.347
Multi-Layer:
  pour cut-out: 110.035,0.028 117.023,0.028 116.971,63.5 110.041,63.5

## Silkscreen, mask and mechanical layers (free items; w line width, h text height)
Top Overlay:
  circle w0.15: c89.803,32.209 r1.13
  circle w0.381: c11.766,1.331 r0.127
  region: 88.447,31.014 88.447,32.239 cw(c89.817,32.239) 89.832,33.609 89.832,33.339 ccw(c89.822,32.284) 88.767,32.284 88.767,32.134 ccw(c89.822,32.134) 89.822,31.079 89.822,31.015
  region: 91.198,31.015 91.198,32.239 ccw(c89.828,32.239) 89.823,33.609 89.823,33.339 cw(c89.823,32.285) 90.878,32.285 90.878,32.134 cw(c89.823,32.134) 89.823,31.079 89.823,31.015
  region: 30.056,58.724 29.718,58.143 29.38,58.724
  region: 26.84,58.143 27.178,58.724 27.516,58.143
  lines w0.15: 15.875,44.646 15.875,40.767 29.046,40.767 ; 15.875,47.338 15.875,50.261 29.07,50.261 ; 15.879,15.494 15.879,11.244 20.675,11.244 ; 15.879,17.526 15.879,26.284 29.075,26.284 29.078,21.174 ; 21.539,11.244 23.851,11.244 ; 24.841,11.244 29.078,11.244 ; 29.07,48.421 29.07,50.253 ; 29.075,11.244 29.075,18.288 ; 29.075,40.767 29.075,45.225 ; 42.204,29.8 42.204,30.3 42.45,30.3 ; 42.204,42.5 42.204,43 42.45,43 ; 42.204,55.2 42.204,55.7 42.45,55.7 ; 45.559,30.3 45.804,30.3 45.804,29.8 ; 45.559,43 45.804,43 45.804,42.5 ; 45.559,55.7 45.804,55.7 45.804,55.2 ; 94,39.125 94,31.15 105.875,31.15 105.875,35.1 ; 94,41.575 94,42.125 101.489,42.125 105.875,42.125 105.875,37.363
  lines w0.178: 27.178,58.039 27.178,58.801 ; 29.718,58.039 29.718,58.801
  lines w0.381: 54.103,0.699 cw(c54.183,0.6) 54.263,0.699
  text "ON" at 0.407,61.167 h1.27
  text "NFC" at 83.126,59.729 h1.8
  text "LED0" at 97.701,59.728 h1.8
  text "LED1" at 103.526,59.728 h1.8
  text "GPIO pins in parentheses are unavailable on headers without modification" at 50.325,59.25 h1.6
  text "VDDM / CURRENT / MEASURE" at 16.649,58.208 h1.8
  text "GND" at 30.525,56.75 h1.52
  text "LED2" at 97.726,56.428 h1.8
  text "LED3" at 103.526,56.428 h1.8
  text "GND" at 42.63,55.215 h1.52
  text "01" at 53.565,55.209 h1.52
  text "03" at 55.965,55.209 h1.52
  text "GND" at 50.24,55.184 h1.52
  text "VDDIO" at 72.512,55.125 h1.52
  text "POWER" at 10.55,54.475 h1.8 r90
  text "OFF" at 0.382,53.592 h1.27
  text "VDDM_nRF" at 92.454,48.175 h1.27 r90
  text "VDD_nRF" at 94.979,48.175 h1.27 r90
  text "DECD" at 97.504,48.175 h1.27 r90
  text "PORT P0" at 50.023,46.672 h1.8 r90
  text "VBUS" at 40.261,45.469 h1.52
  text "00" at 53.487,45.475 h1.52
  text "02" at 56.008,45.47 h1.52
  text "04" at 58.548,45.47 h1.52
  text "GND" at 73.187,45.475 h1.52
  text "VDDIO" at 49.029,45.45 h1.52
  text "GND" at 42.63,42.515 h1.52
  text "GND" at 49.716,42.5 h1.52
  text "09" at 63.687,42.5 h1.52
  text "11" at 66.562,42.5 h1.52
  text "13" at 68.962,42.5 h1.52
  text "05" at 58.523,42.493 h1.52
  text "07" at 61.063,42.493 h1.52
  text "VDDIO" at 72.697,42.493 h1.52
  text "(01)" at 53.241,42.275 h1.52
  text "(03)" at 55.637,42.275 h1.52
  text "nRF54L15" at 93.93,42.15 h1.8
  text "nPM1300" at 15.799,39.042 h1.8
  text ".PCBNumber" at 0.91,38.843 h2.03
  text ".PCBRevision" at 0.91,37.681 h1.52
  text "PORT P1" at 50.023,33.972 h1.8 r90
  text "nRF54L15-DK" at 0.599,33.258 h3
  text "VBUS" at 40.261,32.769 h1.52
  text "VDDIO" at 48.779,32.725 h1.52
  text "04" at 58.548,32.72 h1.52
  text "06" at 61.088,32.72 h1.52
  text "08" at 63.628,32.72 h1.52
  text "10" at 66.345,32.72 h1.52
  text "12" at 68.937,32.725 h1.52
  text "14" at 71.425,32.72 h1.52
  text "GND" at 73.287,32.725 h1.52
  text "(02)" at 55.678,32.517 h1.52
  text "(00)" at 53.066,32.475 h1.52
  text "GND" at 49.64,29.82 h1.52
  text "GND" at 88.447,29.832 h1.4
  text "GND" at 42.63,29.815 h1.52
  text "07" at 61.262,29.8 h1.52
  text "09" at 63.687,29.8 h1.52
  text "VDDIO" at 72.697,29.793 h1.52
  text "(01)" at 53.187,29.575 h1.52
  text "(03)" at 55.662,29.575 h1.52
  text "(05)" at 58.212,29.575 h1.52
  text "DEBUGGER" at 0.587,29.149 h1.8
  text "DEBUGGER" at 15.809,26.224 h1.8
  text "PORT P2" at 50.023,21.272 h1.8 r90
  text "VBUS" at 40.261,20.069 h1.52
  text "VDDIO" at 48.337,20.075 h1.52
  text "06" at 61.088,20.02 h1.52
  text "08" at 63.628,20.02 h1.52
  text "10" at 66.362,20.025 h1.52
  text "GND" at 73.28,20.02 h1.52
  text "(00)" at 53.062,19.825 h1.52
  text "(02)" at 55.662,19.825 h1.52
  text "(04)" at 58.137,19.825 h1.52
  text "BUTTON 0" at 83.896,17.287 h1.8
  text "BUTTON 1" at 94.146,17.287 h1.8
  text "3.6V Max" at 13.085,9.398 h1.4
  text "RESET" at 1.397,9.242 h1.8
  text "DEBUG IN/ TRACE" at 56.904,7.797 h1.8
  text "BUTTON 2" at 83.896,7.786 h1.8
  text "BUTTON 3" at 94.158,7.786 h1.8
  text "DEBUG OUT" at 10.871,7.532 h1.8
  text "GND" at 35.957,6.572 h1.4
  text "GND" at 35.951,1.118 h1.4
Bottom Overlay:
  drawing of 380 lines, arcs and shapes, not listed
  text "GPIO" at 69.872,51.015 h1.78 r180
  text "NFC2" at 56.066,50.036 h1.91 r180
  text "P1.03" at 49.107,50.012 h1.91 r180
  text "0R" at 73.594,48.666 h1.52 r180
  text "N.C." at 69.969,47.976 h1.52 r180
  text "NFC" at 74.735,46.969 h1.78 r180
  text "NFC1" at 56.168,44.881 h1.91 r180
  text "P1.02" at 49.107,44.855 h1.91 r180
  text "PIN" at 71.789,43.873 h1.78 r180
  text "P2.07" at 23.802,41.687 h1.91 r180
  text "SWO" at 31.069,41.699 h1.91 r180
  text "nRF54" at 38.559,41.538 h2.03 r180
  text "SB6" at 63.141,40.893 h1.91 r180
  text "P1.01" at 49.171,39.507 h1.91 r180
  text "XL2" at 56.689,39.485 h1.91 r180
  text "SWDCLK" at 29.523,39.224 h1.91 r180
  text "GPIO" at 69.872,38.471 h1.78 r180
  text "SB4" at 63.141,38.201 h1.91 r180
  text "SWDIO" at 30.27,36.674 h1.91 r180
  text "SB5" at 63.141,35.508 h1.91 r180
  text "DEBUGGER" at 39.111,35.472 h1.4 r180
  text "P1.00" at 49.171,34.122 h1.91 r180
  text "XL1" at 56.791,34.1 h1.91 r180
  text "RESET" at 30.926,34.074 h1.91 r180
  text "PIN" at 75.231,33.923 h1.78 r180
  text "BUTTON 3" at 84.272,33.228 h1.91 r180
  text "SB3" at 63.141,32.816 h1.91 r180
  text "P0.04" at 79.108,32.609 h1.91 r180
  text "CTS1" at 31.278,31.624 h1.91 r180
  text "P1.07" at 23.819,31.619 h1.91 r180
  text "GPIO" at 48.713,30.727 h1.99 r180
  text "Function" at 54.206,30.727 h1.99 r180
  text "Short" at 63.191,30.727 h1.99 r180
  text "HW" at 71.777,30.702 h1.99 r180
  text "BUTTON 2" at 84.298,30.558 h1.91 r180
  text "P1.08" at 79.108,29.909 h1.91 r180
  text "RTS1" at 31.371,29.084 h1.91 r180
  text "P1.06" at 23.819,29.079 h1.91 r180
  text "nRF54" at 38.606,28.511 h2.03 r180
  text "BUTTON 1" at 84.298,27.854 h1.91 r180
  text "SB16/17" at 62.747,27.376 h1.91 r180
  text "P1.09" at 79.104,27.232 h1.91 r180
  text "P2.00" at 49.158,27.216 h1.91 r180
  text "DIO3" at 56.32,27.217 h1.91 r180
  text "P1.04" at 23.819,26.539 h1.91 r180
  text "TXD1" at 31.135,26.54 h1.91 r180
  text "GPIO" at 92.825,25.733 h1.78 r180
  text "BUTTON 0" at 84.265,25.202 h1.91 r180
  text "SB15/20" at 62.797,24.683 h1.91 r180
  text "PIN" at 38.458,24.51 h1.78 r180
  text "P2.03" at 49.158,24.524 h1.91 r180
  text "DIO2" at 56.346,24.524 h1.91 r180
  text "P1.13" at 79.108,24.509 h1.91 r180
  text "P1.05" at 23.819,23.999 h1.91 r180
  text "RXD1" at 31.124,24 h1.91 r180
  text "GPIO" at 69.884,22.054 h1.52 r180
  text "SB14/21" at 62.797,21.991 h1.91 r180
  text "MEM" at 74.575,21.96 h1.52 r180
  text "P1.14" at 79.104,21.847 h1.91 r180
  text "P2.04" at 49.158,21.832 h1.91 r180
  text "DIO1" at 56.422,21.832 h1.91 r180
  text "LED 3" at 85.835,21.834 h1.91 r180
  text "CTS0" at 31.01,21.465 h1.91 r180
  text "P0.03" at 23.819,21.46 h1.91 r180
  text "1M" at 93.863,20.269 h1.52 r180
  text "SBx/" at 72.703,19.932 h1.52 r180
  text "SB13/19" at 62.797,19.298 h1.91 r180
  text "P2.07" at 79.104,19.154 h1.91 r180
  text "LED 2" at 85.835,19.154 h1.91 r180
  text "P2.02" at 49.183,19.139 h1.91 r180
  text "DIO0" at 56.32,19.116 h1.91 r180
  text "RTS0" at 31.103,18.925 h1.91 r180
  text "P0.02" at 23.819,18.92 h1.91 r180
  text "GPIO" at 92.833,17.621 h1.78 r180
  text "/SBx" at 71.875,17.564 h1.52 r180
  text "PIN" at 75.55,17.435 h1.52 r180
  text "DEBUGGER" at 39.156,16.998 h1.4 r180
  text "SB12/18" at 62.797,16.606 h1.91 r180
  text "P1.10" at 79.104,16.462 h1.91 r180
  text "P2.01" at 49.158,16.447 h1.91 r180
  text "CLK" at 56.473,16.447 h1.91 r180
  text "LED 1" at 85.835,16.438 h1.91 r180
  text "P0.00" at 23.819,16.38 h1.91 r180
  text "TXD0" at 30.868,16.369 h1.91 r180
  text "LED 0" at 85.847,14.571 h1.91 r180
  text "SB11/22" at 62.797,13.914 h1.91 r180
  text "P0.01" at 23.819,13.84 h1.91 r180
  text "RXD0" at 30.856,13.829 h1.91 r180
  text "P2.09" at 79.104,13.77 h1.91 r180
  text "P2.05" at 49.158,13.754 h1.91 r180
  text "CS" at 57.082,13.755 h1.91 r180
  text "3.3V" at 97.538,13.344 h1.52 r180
  text "GPIO" at 48.734,11.681 h1.99 r180
  text "Function" at 54.206,11.681 h1.99 r180
  text "Short" at 63.282,11.681 h1.99 r180
  text "HW" at 71.922,11.666 h1.99 r180
  text "GPIO" at 78.681,11.681 h1.99 r180
  text "Function" at 84.152,11.681 h1.99 r180
  text "HW" at 94.63,11.666 h1.99 r180
  text "GPIO" at 23.792,11.289 h2.03 r180
  text "Function" at 29.676,11.286 h2.03 r180
  text "Circuit" at 40.097,11.28 h2.03 r180
Top Paste:
  circle w1.1: c89.803,32.209 r0.25
Top Solder:
  circle w1.4: c89.803,32.209 r0.25
Board Outline:
  the board outline again, w0.254
Top Impedance Info:
  lines w0.153: 7.489,24.375 cw(c7.727,24.137) 7.727,24.473 10.361,24.473 cw(c10.361,24.165) 10.579,24.383 ; 7.489,24.875 ccw(c7.727,25.113) 7.727,24.776 10.322,24.776 ccw(c10.322,25.141) 10.579,24.883 ; 11.579,24.383 cw(c11.801,24.161) 11.801,24.475 11.879,24.475 13.05,24.475 13.084,24.475 cw(c13.084,22.81) 14.75,22.81 14.75,21.422 ccw(c16.6,21.422) 16.6,19.572 19.033,19.572 cw(c19.033,19.138) 19.467,19.138 19.467,18.664 19.46,18.664 ; 11.579,24.883 ccw(c11.833,25.137) 11.833,24.778 11.879,24.778 13.05,24.778 13.084,24.778 cw(c13.084,22.81) 15.053,22.81 15.053,21.422 ccw(c16.6,21.422) 16.6,19.875 19.033,19.875 cw(c19.033,19.138) 19.77,19.138 19.77,18.755 ccw(c19.86,18.755) 19.86,18.664
  text "90-ohms grounded coplanar differential" at 7.452,25.664 h0.64
Bottom Placement:
  circle w0.15: c19.122,29.997 r0.95
  circle w0.15: c38.919,42.395 r0.95
  circle w0.15: c26.334,48.26 r0.95
  circle w0.15: c15.447,44.856 r0.95
  circle w0.15: c23.62,4.115 r0.95
  circle w0.15: c20.62,4.115 r0.95
  circle w0.15: c26.62,4.115 r0.95
  circle w0.15: c29.62,4.115 r0.95
  circle w0.15: c16.004,2 r0.95
  circle w0.15: c9.135,12.15 r0.95
  circle w0.15: c10.24,23.113 r0.95
  circle w0.15: c10.24,26.115 r0.95
  circle w0.15: c13.263,23.571 r0.95
  circle w0.15: c16.032,27.61 r0.95
  circle w0.15: c21.797,27.432 r0.95
  circle w0.15: c24.797,28.423 r0.95
  circle w0.15: c27.797,28.423 r0.95
  circle w0.15: c37.215,26.746 r0.95
  circle w0.15: c37.215,21.746 r0.95
  circle w0.15: c37.215,16.746 r0.95
  circle w0.15: c37.215,11.746 r0.95
  circle w0.15: c45.496,13.056 r0.95
  circle w0.15: c9.25,31.75 r0.95
  circle w0.15: c10.24,38.353 r0.95
  circle w0.15: c10.24,41.353 r0.95
  circle w0.15: c13.263,38.845 r0.95
  circle w0.15: c32.034,37.567 r0.95
  circle w0.15: c37.418,38.711 r0.95
  circle w0.15: c38.104,47.219 r0.95
  circle w0.15: c36.174,49.2 r0.95
  circle w0.15: c10.698,48.92 r0.95
  circle w0.15: c14.533,54.305 r0.95
  circle w0.15: c18.622,57.582 r0.95
  circle w0.15: c22.077,54.813 r0.95
  circle w0.15: c26.877,54.915 r0.95
  circle w0.15: c23.372,58.039 r0.95
  text "Circles mark PCA10145 v0.9.0 test point locations" at 9.793,61.805 h0.6

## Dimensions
0.029,63.5 to 12.6,58.5 on Dimension
0,0 to 8.004,5 on Dimension
0,63.856 to 12.6,58.5 on Dimension
0,0 to 8,5 on Dimension
113.104,58.5 to 106.004,5 on Dimension
44.004,5 to 106.004,5 on Dimension
8.004,5 to 44.004,5 on Dimension
44.004,58.5 to 113.104,58.5 on Dimension
12.604,58.5 to 44.004,58.5 on Dimension
0,0 to 0,63.5 on Dimension
0,0 to 117.004,0 on Dimension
